FUNCTION FC 38 : VOID
  BEGIN
  NETWORK
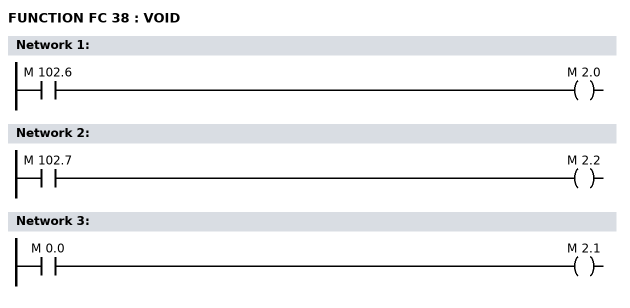
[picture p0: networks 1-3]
       A   M 102.6;
       =   M 2.0;
  NETWORK
       A   M 102.7;
       =   M 2.2;
  NETWORK
       A   M 0.0;
       =   M 2.1;
  NETWORK


END_FUNCTION

FUNCTION FC 39 : VOID
  BEGIN
  NETWORK
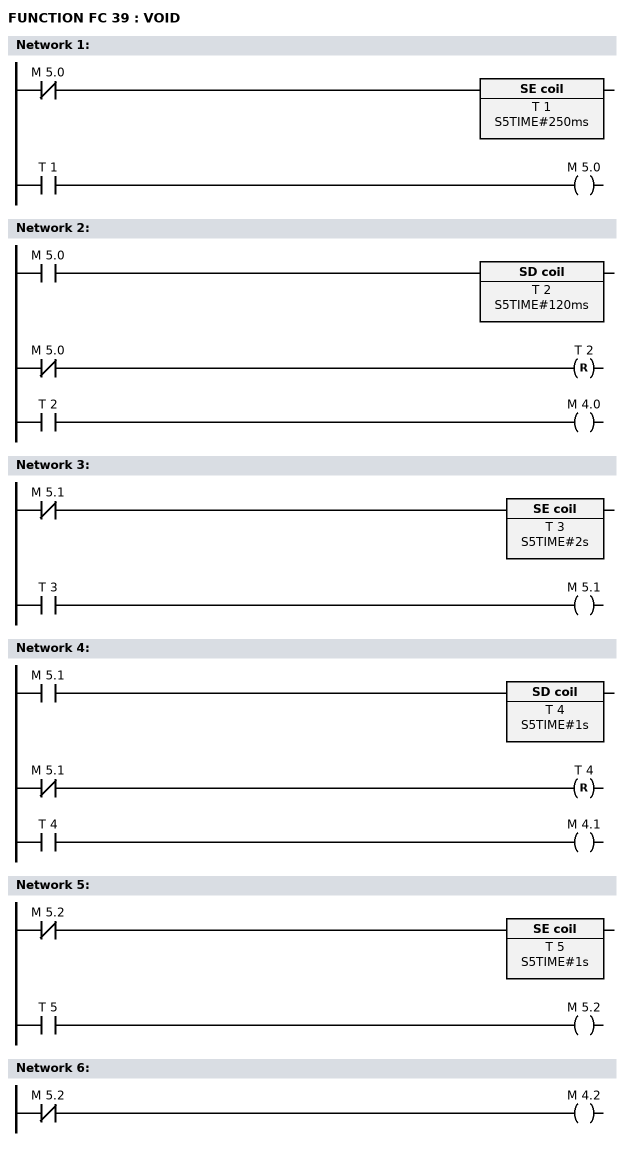
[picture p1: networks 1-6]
       AN  M 5.0;
       L   S5TIME#250ms;
       SE  T 1;
       NOP 0;
       NOP 0;
       NOP 0;
       A   T 1;
       =   M 5.0;
  NETWORK
       A   M 5.0;
       L   S5TIME#120ms;
       SD  T 2;
       AN  M 5.0;
       R   T 2;
       NOP 0;
       NOP 0;
       A   T 2;
       =   M 4.0;
  NETWORK
       AN  M 5.1;
       L   S5TIME#2s;
       SE  T 3;
       NOP 0;
       NOP 0;
       NOP 0;
       A   T 3;
       =   M 5.1;
  NETWORK
       A   M 5.1;
       L   S5TIME#1s;
       SD  T 4;
       AN  M 5.1;
       R   T 4;
       NOP 0;
       NOP 0;
       A   T 4;
       =   M 4.1;
  NETWORK
       AN  M 5.2;
       L   S5TIME#1s;
       SE  T 5;
       NOP 0;
       NOP 0;
       NOP 0;
       A   T 5;
       =   M 5.2;
  NETWORK
       AN  M 5.2;
       =   M 4.2;
  NETWORK


END_FUNCTION

FUNCTION FC 40 : VOID
  BEGIN
  NETWORK
       //;
       AN  M 126.0;
       JCN   X000;
     CALL FC 33;
  X000: NOP 0;
       S   M 126.0;
       //;
       L   W#16#0;
       T   MB 202;
       //;
       //;


END_FUNCTION

FUNCTION FC 41 : VOID
  BEGIN
  NETWORK
       OPN DB 9;
       L   DBW 20;
       T   MW 250;
       L   DBW 22;
       T   MW 252;
       L   DBW 26;
       T   MW 246;
       L   DBW 28;
       T   MW 248;
       //;
       OPN DB 94;
  NETWORK
       A(;
       A   I 14.1;
       =   M 251.0;
       A   M 251.0;
       );
       A   M 250.0;
       S   M 48.1;
  NETWORK
       AN  M 250.0;
       A(;
       AN  M 251.0;
       =   M 250.0;
       A   M 250.0;
       );
       S   M 48.2;
  NETWORK
       A(;
       A   I 14.3;
       =   M 251.2;
       A   M 251.2;
       );
       A   M 250.2;
       S   M 52.1;
  NETWORK
       AN  M 250.2;
       A(;
       AN  M 251.2;
       =   M 250.2;
       A   M 250.2;
       );
       S   M 52.2;
  NETWORK
       AN  M 250.3;
       A(;
       AN  M 181.6;
       =   M 250.3;
       A   M 250.3;
       );
       S   M 66.1;
  NETWORK
       AN  M 251.3;
       A(;
       A   M 181.6;
       =   M 251.3;
       A   M 251.3;
       );
       S   M 66.2;
  NETWORK
       AN  M 250.4;
       A(;
       A   I 29.4;
       A   I 29.5;
       =   M 250.4;
       A   M 250.4;
       );
       S   M 70.1;
  NETWORK
       AN  M 251.4;
       A(;
       AN  I 29.5;
       =   M 251.4;
       A   M 251.4;
       );
       S   M 70.2;
  NETWORK
       AN  M 250.5;
       A(;
       A   I 30.1;
       A   I 36.4;
       =   M 250.5;
       A   M 250.5;
       );
       S   M 71.1;
  NETWORK
       AN  M 251.5;
       A(;
       AN  I 36.4;
       =   M 251.5;
       A   M 251.5;
       );
       S   M 71.2;
  NETWORK
       AN  M 250.5;
       A(;
       A   I 36.6;
       A   I 36.7;
       =   M 250.5;
       A   M 250.5;
       );
       S   M 82.1;
  NETWORK
       AN  M 251.4;
       A(;
       AN  I 36.7;
       =   M 251.4;
       A   M 251.4;
       );
       S   M 82.2;
  NETWORK
       A(;
       O   M 104.0;
       L   DBW 150;
       SF  T 75;
       NOP 0;
       NOP 0;
       NOP 0;
       A   T 75;
       );
       A(;
       O   I 7.1;
       O;
       AN  I 7.0;
       A   M 108.0;
       );
       =   M 253.2;
       A   M 253.2;
       A   M 252.2;
       S   M 114.1;
  NETWORK
       AN  M 252.2;
       A(;
       AN  M 253.2;
       =   M 252.2;
       A   M 252.2;
       );
       S   M 114.2;
  NETWORK
       A(;
       O   M 104.1;
       L   DBW 152;
       SF  T 76;
       NOP 0;
       NOP 0;
       NOP 0;
       A   T 76;
       );
       A(;
       O   I 7.3;
       O;
       AN  I 7.2;
       A   M 108.1;
       );
       =   M 253.3;
       A   M 253.3;
       A   M 252.3;
       S   M 115.1;
  NETWORK
       AN  M 252.3;
       A(;
       AN  M 253.3;
       =   M 252.3;
       A   M 252.3;
       );
       S   M 115.2;
  NETWORK
       A   M 102.1;
       S   M 105.5;
       OPN DB 100;
       A   DBX 24.2;
       R   M 105.5;
  NETWORK
       AN  M 253.4;
       A(;
       A(;
       A   I 25.7;
       L   DBW 218;
       SD  T 109;
       NOP 0;
       NOP 0;
       NOP 0;
       A   T 109;
       );
       AN  M 105.5;
       =   M 253.4;
       A   M 253.4;
       );
       S   M 122.1;
  NETWORK
       AN  M 252.4;
       A(;
       O   M 105.5;
       =   M 252.4;
       A   M 252.4;
       );
       S   M 122.2;
  NETWORK
       AN  M 252.5;
       A(;
       A   M 178.6;
       =   M 252.5;
       A   M 252.5;
       );
       S   M 116.1;
  NETWORK
       AN  M 252.5;
       A(;
       A(;
       AN  M 179.6;
       L   DBW 220;
       SF  T 110;
       NOP 0;
       NOP 0;
       NOP 0;
       A   T 110;
       );
       =   M 252.5;
       A   M 252.5;
       );
       S   M 116.2;
  NETWORK
       OPN DB 110;
       A   DBX 42.0;
       =   M 252.7;
  NETWORK
       OPN DB 94;
       AN  M 252.6;
       A(;
       A(;
       AN  Q 0.2;
       L   DBW 222;
       SD  T 111;
       NOP 0;
       NOP 0;
       NOP 0;
       A   T 111;
       );
       A   M 252.7;
       =   M 252.6;
       A   M 252.6;
       );
       S   M 121.1;
  NETWORK
       AN  M 252.6;
       A(;
       A(;
       A   Q 0.2;
       L   DBW 224;
       SD  T 112;
       NOP 0;
       NOP 0;
       NOP 0;
       A   T 112;
       );
       A   M 252.7;
       =   M 252.6;
       A   M 252.6;
       );
       S   M 121.2;
  NETWORK
       //;
  NETWORK
       AN  M 246.0;
       A(;
       A   I 3.4;
       =   M 246.0;
       A   M 246.0;
       );
       S   M 68.1;
  NETWORK
       //;
       AN  M 247.0;
       A(;
       AN  I 0.6;
       =   M 247.0;
       A   M 247.0;
       );
       S   M 68.2;
  NETWORK
       AN  M 246.1;
       A(;
       A   I 0.2;
       =   M 246.1;
       A   M 246.1;
       );
       S   M 42.1;
  NETWORK
       AN  M 247.1;
       A(;
       AN  I 0.0;
       =   M 247.1;
       A   M 247.1;
       );
       S   M 42.2;
  NETWORK
       AN  M 246.2;
       A(;
       A   I 0.2;
       =   M 246.2;
       A   M 246.2;
       );
       S   M 43.1;
  NETWORK
       //;
       AN  M 247.2;
       A(;
       AN  I 0.0;
       =   M 247.2;
       A   M 247.2;
       );
       S   M 43.2;
  NETWORK
       A(;
       AN  M 0.1;
       =   M 247.3;
       A   M 247.3;
       );
       A   M 246.3;
       S   M 123.1;
  NETWORK
       //;
       AN  M 246.3;
       A(;
       AN  M 247.3;
       =   M 246.3;
       A   M 246.3;
       );
       S   M 123.2;
  NETWORK
       AN  M 247.4;
       A(;
       AN  I 29.0;
       =   M 247.4;
       A   M 247.4;
       );
       A   M 247.4;
       S   M 118.2;
  NETWORK
       //;
       AN  M 246.4;
       A(;
       A   I 29.1;
       =   M 246.4;
       A   M 246.4;
       );
       S   M 118.1;
  NETWORK
       AN  M 247.5;
       A(;
       AN  I 29.0;
       =   M 247.5;
       A   M 247.5;
       );
       A   M 247.5;
       S   M 119.2;
  NETWORK
       //;
       AN  M 246.5;
       A(;
       A   I 29.1;
       =   M 246.5;
       A   M 246.5;
       );
       S   M 119.1;
       //;
  NETWORK
       OPN DB 9;
       L   MW 250;
       T   DBW 20;
       L   MW 252;
       T   DBW 22;
       L   MW 246;
       T   DBW 26;
       L   MW 248;
       T   DBW 28;
       //;
       OPN DB 94;
  NETWORK
       //;
       //;
       //;
       //;
       //;
       //;
       //;
       //;
  NETWORK


END_FUNCTION

FUNCTION FC 42 : VOID
  BEGIN
  NETWORK
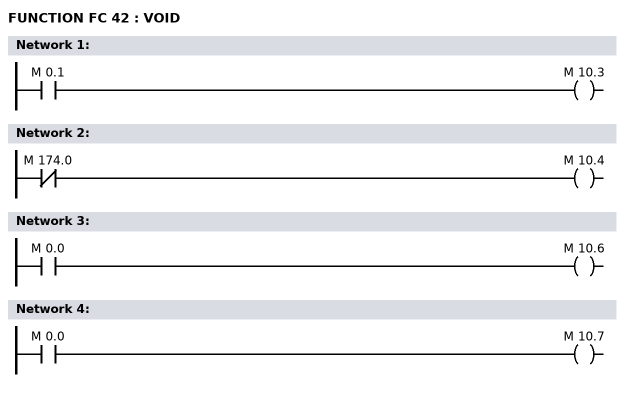
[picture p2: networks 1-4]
       O   M 0.1;
       =   M 10.3;
  NETWORK
       AN  M 174.0;
       =   M 10.4;
  NETWORK
       A   M 0.0;
       =   M 10.6;
  NETWORK
       A   M 0.0;
       =   M 10.7;
  NETWORK
       OPN DB 100;
       L   DBW 20;
       T   MW 206;
       L   DBW 220;
       T   MW 204;
       L   MB 10;
       T   MB 200;
       A   Q 5.6;
       =   M 201.0;
       A   M 2.1;
       =   M 201.1;
       A   I 26.7;
       =   M 201.2;
       A   M 0.0;
       =   M 201.3;
  NETWORK
       CALL FC 15;
  NETWORK
       A   M 201.0;
       =   Q 5.6;
       L   MB 200;
       T   MB 10;
       L   MW 204;
       T   DBW 220;
       L   MW 206;
       T   DBW 20;
  NETWORK
       OPN DB 108;
       L   MB 202;
       T   DBB 21;


END_FUNCTION

FUNCTION FC 43 : VOID
  BEGIN
  NETWORK
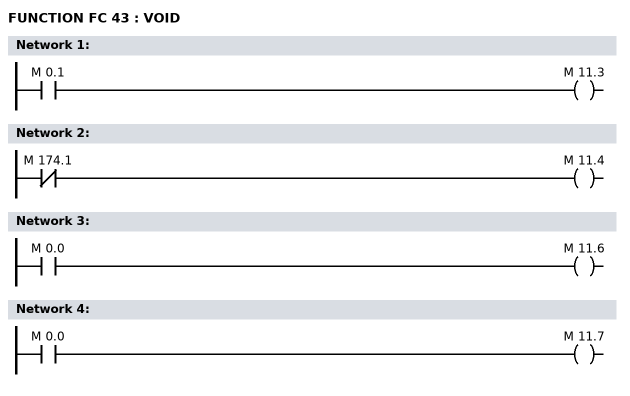
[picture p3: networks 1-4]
       A   M 0.1;
       =   M 11.3;
  NETWORK
       AN  M 174.1;
       =   M 11.4;
  NETWORK
       A   M 0.0;
       =   M 11.6;
  NETWORK
       A   M 0.0;
       =   M 11.7;
  NETWORK
       OPN DB 100;
       L   DBW 22;
       T   MW 206;
       L   DBW 222;
       T   MW 204;
       L   MB 11;
       T   MB 200;
       A   Q 10.4;
       =   M 201.0;
       A   M 2.1;
       =   M 201.1;
       A   I 27.7;
       =   M 201.2;
       A   M 0.0;
       =   M 201.3;
  NETWORK
       CALL FC 15;
  NETWORK
       A   M 201.0;
       =   Q 10.4;
       L   MB 200;
       T   MB 11;
       L   MW 204;
       T   DBW 222;
       L   MW 206;
       T   DBW 22;
  NETWORK
       OPN DB 108;
       L   MB 202;
       T   DBB 20;
END_FUNCTION


FUNCTION FC 44 : VOID
  BEGIN
  NETWORK
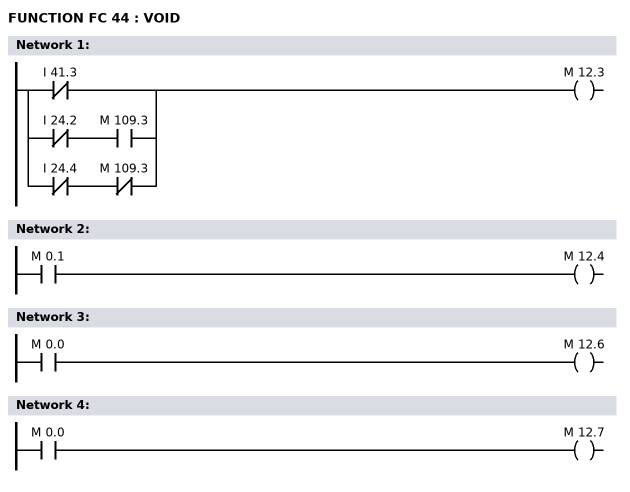
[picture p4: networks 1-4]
       ON  I 41.3;
       O(;
       AN  I 24.2;
       A   M 109.3;
       );
       O(;
       ON  I 24.4;
       AN  M 109.3;
       );
       =   M 12.3;
  NETWORK
       A   M 0.1;
       =   M 12.4;
  NETWORK
       A   M 0.0;
       =   M 12.6;
  NETWORK
       A   M 0.0;
       =   M 12.7;
  NETWORK
       OPN DB 100;
       L   DBW 24;
       T   MW 206;
       L   DBW 224;
       T   MW 204;
       L   MB 12;
       T   MB 200;
       A   Q 4.0;
       =   M 201.0;
       A   M 2.1;
       =   M 201.1;
       A   I 25.7;
       =   M 201.2;
       A   M 0.0;
       =   M 201.3;
  NETWORK
       CALL FC 15;
  NETWORK
       A   M 201.0;
       =   Q 4.0;
       L   MB 200;
       T   MB 12;
       L   MW 204;
       T   DBW 224;
       L   MW 206;
       T   DBW 24;
  NETWORK
       OPN DB 108;
       L   MB 202;
       T   DBB 23;


END_FUNCTION

FUNCTION FC 45 : VOID
  BEGIN
  NETWORK
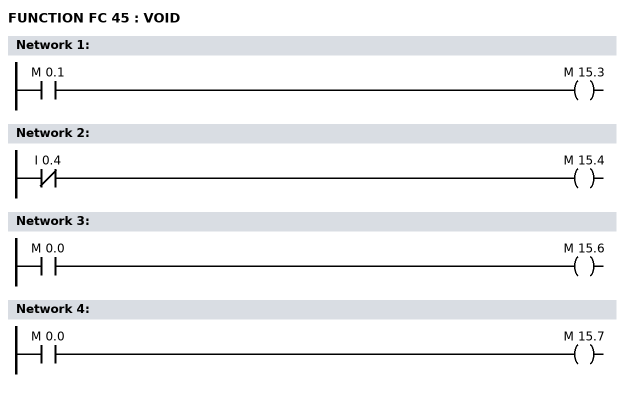
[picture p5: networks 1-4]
       A   M 0.1;
       =   M 15.3;
  NETWORK
       AN  I 0.4;
       =   M 15.4;
  NETWORK
       A   M 0.0;
       =   M 15.6;
  NETWORK
       A   M 0.0;
       =   M 15.7;
  NETWORK
       OPN DB 100;
       L   DBW 30;
       T   MW 206;
       L   DBW 230;
       T   MW 204;
       L   MB 15;
       T   MB 200;
       A   Q 0.5;
       =   M 201.0;
       A   M 2.1;
       =   M 201.1;
       A   I 0.5;
       =   M 201.2;
       A   M 0.0;
       =   M 201.3;
  NETWORK
       CALL FC 15;
  NETWORK
       A   M 201.0;
       =   Q 0.5;
       L   MB 200;
       T   MB 15;
       L   MW 204;
       T   DBW 230;
       L   MW 206;
       T   DBW 30;
  NETWORK
       OPN DB 108;
       L   MB 202;
       T   DBB 24;


END_FUNCTION

FUNCTION FC 46 : VOID
  BEGIN
  NETWORK
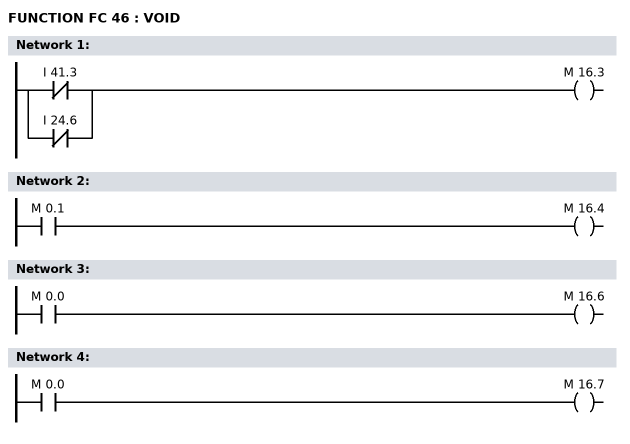
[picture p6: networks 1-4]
       ON  I 41.3;
       ON  I 24.6;
       =   M 16.3;
  NETWORK
       A   M 0.1;
       =   M 16.4;
  NETWORK
       A   M 0.0;
       =   M 16.6;
  NETWORK
       A   M 0.0;
       =   M 16.7;
  NETWORK
       OPN DB 100;
       L   DBW 32;
       T   MW 206;
       L   DBW 232;
       T   MW 204;
       L   MB 16;
       T   MB 200;
       A   Q 4.2;
       =   M 201.0;
       A   M 2.1;
       =   M 201.1;
       A   I 26.3;
       =   M 201.2;
       A   M 0.0;
       =   M 201.3;
  NETWORK
       CALL FC 15;
  NETWORK
       A   M 201.0;
       =   Q 4.2;
       L   MB 200;
       T   MB 16;
       L   MW 204;
       T   DBW 232;
       L   MW 206;
       T   DBW 32;
  NETWORK
       OPN DB 108;
       L   MB 202;
       T   DBB 27;


END_FUNCTION

FUNCTION FC 47 : VOID
  BEGIN
  NETWORK
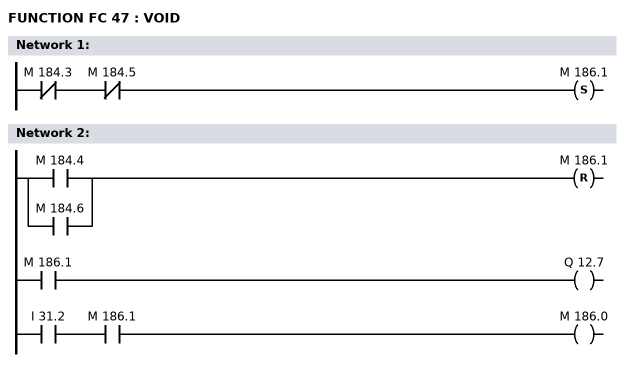
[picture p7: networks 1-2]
       AN  M 184.3;
       AN  M 184.5;
       S   M 186.1;
  NETWORK
       O   M 184.4;
       O   M 184.6;
       R   M 186.1;
       A   M 186.1;
       =   Q 12.7;
       A   I 31.2;
       A   M 186.1;
       =   M 186.0;


END_FUNCTION

FUNCTION FC 48 : VOID
  BEGIN
  NETWORK
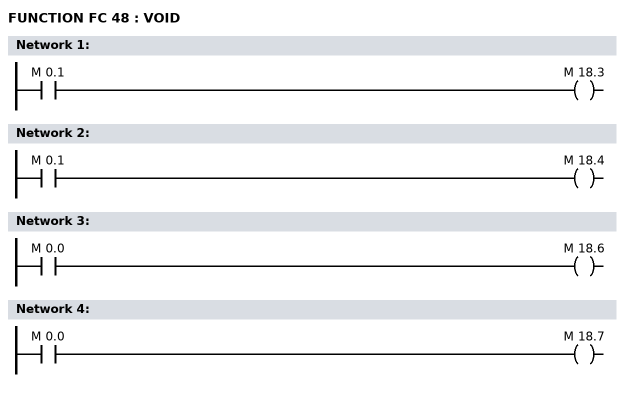
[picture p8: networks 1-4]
       A   M 0.1;
       =   M 18.3;
  NETWORK
       A   M 0.1;
       =   M 18.4;
  NETWORK
       A   M 0.0;
       =   M 18.6;
  NETWORK
       A   M 0.0;
       =   M 18.7;
  NETWORK
       OPN DB 100;
       L   DBW 36;
       T   MW 206;
       L   DBW 236;
       T   MW 204;
       L   MB 18;
       T   MB 200;
       A   Q 1.0;
       =   M 201.0;
       A   M 2.1;
       =   M 201.1;
       A   I 1.0;
       =   M 201.2;
       A   M 0.0;
       =   M 201.3;
  NETWORK
       CALL FC 15;
  NETWORK
       A   M 201.0;
       =   Q 1.0;
       L   MB 200;
       T   MB 18;
       L   MW 204;
       T   DBW 236;
       L   MW 206;
       T   DBW 36;
  NETWORK
       OPN DB 108;
       L   MB 202;
       T   DBB 29;


END_FUNCTION

FUNCTION FC 49 : VOID
  BEGIN
  NETWORK
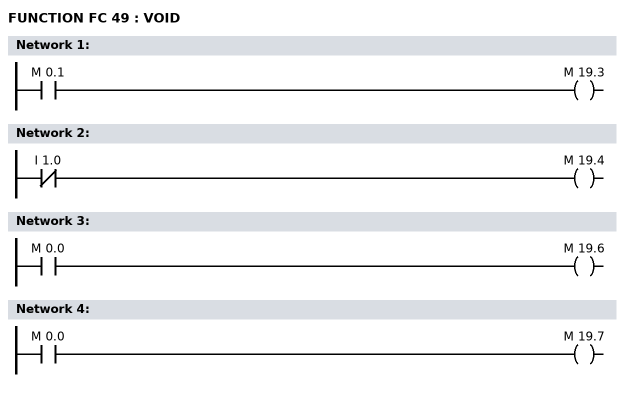
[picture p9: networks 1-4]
       A   M 0.1;
       =   M 19.3;
  NETWORK
       AN  I 1.0;
       =   M 19.4;
  NETWORK
       A   M 0.0;
       =   M 19.6;
  NETWORK
       A   M 0.0;
       =   M 19.7;
  NETWORK
       OPN DB 100;
       L   DBW 38;
       T   MW 206;
       L   DBW 238;
       T   MW 204;
       L   MB 19;
       T   MB 200;
       A   Q 1.1;
       =   M 201.0;
       A   M 2.1;
       =   M 201.1;
       A   I 1.1;
       =   M 201.2;
       A   M 0.0;
       =   M 201.3;
  NETWORK
       CALL FC 15;
  NETWORK
       A   M 201.0;
       =   Q 1.1;
       L   MB 200;
       T   MB 19;
       L   MW 204;
       T   DBW 238;
       L   MW 206;
       T   DBW 38;
  NETWORK
       OPN DB 108;
       L   MB 202;
       T   DBB 28;


END_FUNCTION

FUNCTION FC 50 : VOID
  BEGIN
  NETWORK
       OPN DB 94;
  NETWORK
       AN  I 7.0;
       AN  I 7.1;
       =   M 24.3;
  NETWORK
       O(;
       AN  M 114.4;
       AN  M 114.5;
       L   DBW 40;
       SD  T 20;
       NOP 0;
       NOP 0;
       NOP 0;
       A   T 20;
       );
       ON  I 3.2;
       L   DBW 60;
       SF  T 30;
       NOP 0;
       NOP 0;
       NOP 0;
       A   T 30;
       =   M 24.4;
  NETWORK
       A   M 0.0;
       =   M 24.6;
  NETWORK
       A   M 0.0;
       =   M 24.7;
  NETWORK
       OPN DB 100;
       L   DBW 48;
       T   MW 206;
       L   DBW 248;
       T   MW 204;
       L   MB 24;
       T   MB 200;
       A   Q 1.6;
       =   M 201.0;
       A   M 2.1;
       =   M 201.1;
       A   I 1.6;
       =   M 201.2;
       A   M 0.0;
       =   M 201.3;
  NETWORK
       CALL FC 15;
  NETWORK
       A   M 201.0;
       =   Q 1.6;
       L   MB 200;
       T   MB 24;
       L   MW 204;
       T   DBW 248;
       L   MW 206;
       T   DBW 48;
  NETWORK
       OPN DB 108;
       L   MB 202;
       T   DBB 35;


END_FUNCTION

FUNCTION FC 51 : VOID
  BEGIN
  NETWORK
       OPN DB 94;
  NETWORK
       A   M 0.1;
       =   M 25.3;
  NETWORK
       O(;
       A   I 8.6;
       L   DBW 62;
       SF  T 31;
       NOP 0;
       NOP 0;
       NOP 0;
       A   T 31;
       );
       O;
       AN  M 112.4;
       AN  M 113.5;
       ON  I 3.3;
       L   DBW 90;
       SF  T 45;
       NOP 0;
       NOP 0;
       NOP 0;
       A   T 45;
       =   M 25.4;
  NETWORK
       A   M 0.0;
       =   M 25.6;
  NETWORK
       A   M 0.0;
       =   M 25.7;
  NETWORK
       OPN DB 100;
       L   DBW 50;
       T   MW 206;
       L   DBW 250;
       T   MW 204;
       L   MB 25;
       T   MB 200;
       A   Q 1.7;
       =   M 201.0;
       A   M 2.1;
       =   M 201.1;
       A   I 1.7;
       =   M 201.2;
       A   M 0.0;
       =   M 201.3;
  NETWORK
       CALL FC 15;
  NETWORK
       A   M 201.0;
       =   Q 1.7;
       L   MB 200;
       T   MB 25;
       L   MW 204;
       T   DBW 250;
       L   MW 206;
       T   DBW 50;
  NETWORK
       OPN DB 108;
       L   MB 202;
       T   DBB 34;


END_FUNCTION

FUNCTION FC 52 : VOID
  BEGIN
  NETWORK
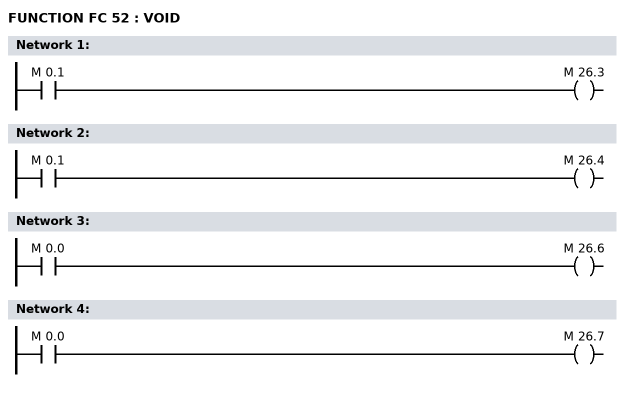
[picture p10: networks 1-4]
       A   M 0.1;
       =   M 26.3;
  NETWORK
       A   M 0.1;
       =   M 26.4;
  NETWORK
       A   M 0.0;
       =   M 26.6;
  NETWORK
       A   M 0.0;
       =   M 26.7;
  NETWORK
       OPN DB 100;
       L   DBW 52;
       T   MW 206;
       L   DBW 252;
       T   MW 204;
       L   MB 26;
       T   MB 200;
       A   Q 2.0;
       =   M 201.0;
       A   M 2.1;
       =   M 201.1;
       A   I 2.0;
       =   M 201.2;
       A   M 0.0;
       =   M 201.3;
  NETWORK
       CALL FC 15;
  NETWORK
       A   M 201.0;
       =   Q 2.0;
       L   MB 200;
       T   MB 26;
       L   MW 204;
       T   DBW 252;
       L   MW 206;
       T   DBW 52;
  NETWORK
       OPN DB 108;
       L   MB 202;
       T   DBB 37;


END_FUNCTION

FUNCTION FC 53 : VOID
  BEGIN
  NETWORK
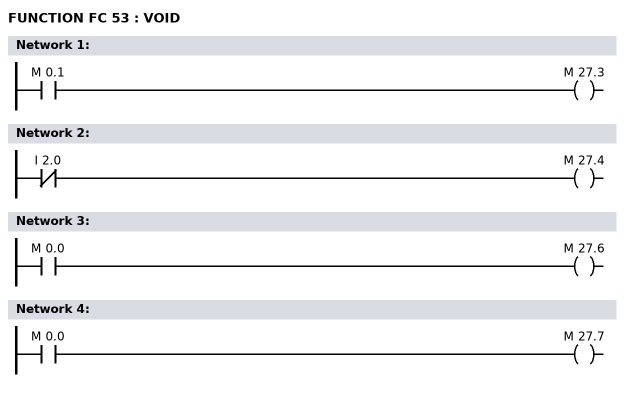
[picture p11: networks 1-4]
       A   M 0.1;
       =   M 27.3;
  NETWORK
       AN  I 2.0;
       =   M 27.4;
  NETWORK
       A   M 0.0;
       =   M 27.6;
  NETWORK
       A   M 0.0;
       =   M 27.7;
  NETWORK
       OPN DB 100;
       L   DBW 54;
       T   MW 206;
       L   DBW 254;
       T   MW 204;
       L   MB 27;
       T   MB 200;
       O   Q 2.1;
       =   M 201.0;
       A   M 2.1;
       =   M 201.1;
       A   I 2.1;
       =   M 201.2;
       A   M 0.0;
       =   M 201.3;
  NETWORK
       CALL FC 15;
  NETWORK
       A   M 201.0;
       =   Q 2.1;
       L   MB 200;
       T   MB 27;
       L   MW 204;
       T   DBW 254;
       L   MW 206;
       T   DBW 54;
  NETWORK
       OPN DB 108;
       L   MB 202;
       T   DBB 36;


END_FUNCTION

FUNCTION FC 54 : VOID
  BEGIN
  NETWORK
       OPN DB 94;
  NETWORK
       AN  I 7.2;
       AN  I 7.3;
       =   M 35.3;
  NETWORK
       O(;
       AN  M 115.4;
       AN  M 115.5;
       L   DBW 70;
       SD  T 35;
       NOP 0;
       NOP 0;
       NOP 0;
       A   T 35;
       );
       O;
       ON  I 3.3;
       L   DBW 72;
       SF  T 36;
       NOP 0;
       NOP 0;
       NOP 0;
       A   T 36;
       =   M 35.4;
  NETWORK
       A   M 0.0;
       =   M 35.6;
  NETWORK
       A   M 0.0;
       =   M 35.7;
  NETWORK
       OPN DB 100;
       L   DBW 70;
       T   MW 206;
       L   DBW 270;
       T   MW 204;
       L   MB 35;
       T   MB 200;
       A   Q 3.1;
       =   M 201.0;
       A   M 2.1;
       =   M 201.1;
       A   I 3.1;
       =   M 201.2;
       A   M 0.0;
       =   M 201.3;
  NETWORK
       CALL FC 15;
  NETWORK
       A   M 201.0;
       =   Q 3.1;
       L   MB 200;
       T   MB 35;
       L   MW 204;
       T   DBW 270;
       L   MW 206;
       T   DBW 70;
  NETWORK
       OPN DB 108;
       L   MB 202;
       T   DBB 44;


END_FUNCTION

FUNCTION FC 55 : VOID
  BEGIN
  NETWORK
       OPN DB 94;
  NETWORK
       A   M 0.1;
       =   M 36.3;
  NETWORK
       A(;
       AN  I 7.0;
       AN  I 7.1;
       L   DBW 74;
       SD  T 37;
       NOP 0;
       NOP 0;
       NOP 0;
       A   T 37;
       );
       ON  I 1.1;
       =   M 36.4;
  NETWORK
       A   M 0.0;
       =   M 36.6;
  NETWORK
       AN  I 1.6;
       =   M 36.7;
  NETWORK
       OPN DB 100;
       L   DBW 72;
       T   MW 206;
       L   DBW 272;
       T   MW 204;
       L   MB 36;
       T   MB 200;
       A   Q 3.2;
       =   M 201.0;
       A   M 2.1;
       =   M 201.1;
       A   I 3.2;
       =   M 201.2;
       A   M 0.0;
       =   M 201.3;
  NETWORK
       CALL FC 15;
  NETWORK
       A   M 201.0;
       =   Q 3.2;
       L   MB 200;
       T   MB 36;
       L   MW 204;
       T   DBW 272;
       L   MW 206;
       T   DBW 72;
  NETWORK
       OPN DB 108;
       L   MB 202;
       T   DBB 47;


END_FUNCTION

FUNCTION FC 56 : VOID
  BEGIN
  NETWORK
       OPN DB 94;
  NETWORK
       A   M 0.1;
       =   M 37.3;
  NETWORK
       O(;
       AN  I 7.6;
       AN  I 7.7;
       L   DBW 80;
       SF  T 40;
       NOP 0;
       NOP 0;
       NOP 0;
       A   T 40;
       );
       ON  I 2.1;
       =   M 37.4;
  NETWORK
       A   M 0.0;
       =   M 37.6;
  NETWORK
       AN  I 3.1;
       =   M 37.7;
  NETWORK
       OPN DB 100;
       L   DBW 74;
       T   MW 206;
       L   DBW 274;
       T   MW 204;
       L   MB 37;
       T   MB 200;
       A   Q 3.3;
       =   M 201.0;
       A   M 2.1;
       =   M 201.1;
       A   I 3.3;
       =   M 201.2;
       A   M 0.0;
       =   M 201.3;
  NETWORK
       CALL FC 15;
  NETWORK
       A   M 201.0;
       =   Q 3.3;
       L   MB 200;
       T   MB 37;
       L   MW 204;
       T   DBW 274;
       L   MW 206;
       T   DBW 74;
  NETWORK
       OPN DB 108;
       L   MB 202;
       T   DBB 46;


END_FUNCTION

FUNCTION FC 57 : VOID
  BEGIN
  NETWORK
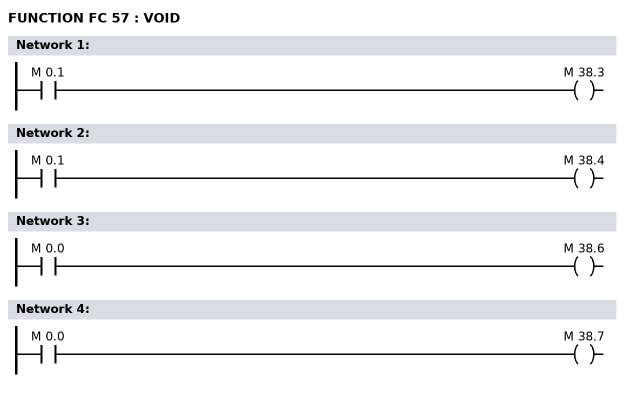
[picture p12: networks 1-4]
       A   M 0.1;
       =   M 38.3;
  NETWORK
       A   M 0.1;
       =   M 38.4;
  NETWORK
       A   M 0.0;
       =   M 38.6;
  NETWORK
       A   M 0.0;
       =   M 38.7;
  NETWORK
       OPN DB 100;
       L   DBW 76;
       T   MW 206;
       L   DBW 276;
       T   MW 204;
       L   MB 38;
       T   MB 200;
       A   Q 3.4;
       =   M 201.0;
       A   M 2.1;
       =   M 201.1;
       A   I 3.4;
       =   M 201.2;
       A   M 0.0;
       =   M 201.3;
  NETWORK
       CALL FC 15;
  NETWORK
       A   M 201.0;
       =   Q 3.4;
       L   MB 200;
       T   MB 38;
       L   MW 204;
       T   DBW 276;
       L   MW 206;
       T   DBW 76;
  NETWORK
       OPN DB 108;
       L   MW 202;
       T   DBB 49;


END_FUNCTION

FUNCTION FC 58 : VOID
  BEGIN
  NETWORK
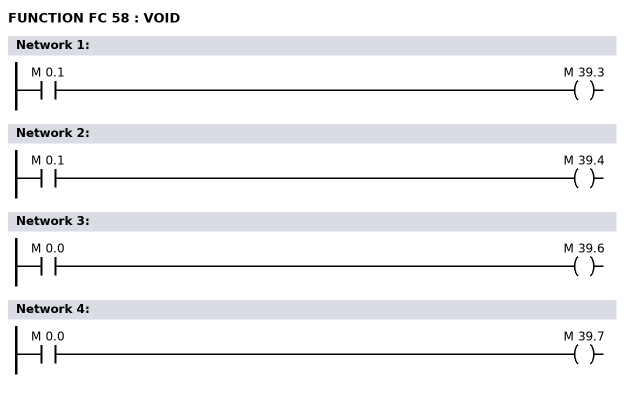
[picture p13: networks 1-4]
       A   M 0.1;
       =   M 39.3;
  NETWORK
       A   M 0.1;
       =   M 39.4;
  NETWORK
       A   M 0.0;
       =   M 39.6;
  NETWORK
       A   M 0.0;
       =   M 39.7;
  NETWORK
       OPN DB 100;
       L   DBW 78;
       T   MW 206;
       L   DBW 278;
       T   MW 204;
       L   MB 39;
       T   MB 200;
       A   Q 3.5;
       =   M 201.0;
       A   M 2.1;
       =   M 201.1;
       A   I 3.5;
       =   M 201.2;
       A   M 0.0;
       =   M 201.3;
  NETWORK
       CALL FC 15;
  NETWORK
       A   M 201.0;
       =   Q 3.5;
       L   MB 200;
       T   MB 39;
       L   MW 204;
       T   DBW 278;
       L   MW 206;
       T   DBW 78;
  NETWORK
       OPN DB 108;
       L   MW 202;
       T   DBB 48;


END_FUNCTION

FUNCTION FC 59 : VOID
  BEGIN
  NETWORK
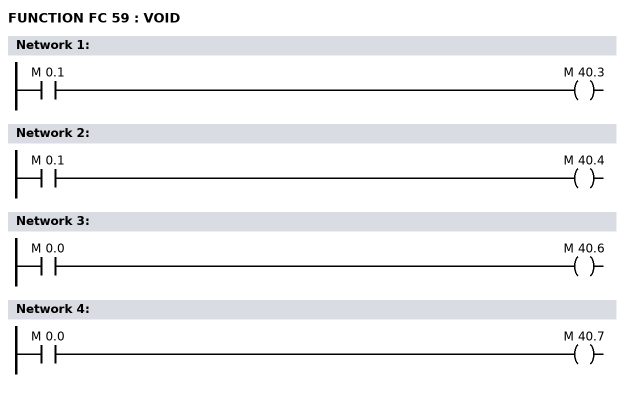
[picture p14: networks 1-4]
       A   M 0.1;
       =   M 40.3;
  NETWORK
       A   M 0.1;
       =   M 40.4;
  NETWORK
       A   M 0.0;
       =   M 40.6;
  NETWORK
       A   M 0.0;
       =   M 40.7;
  NETWORK
       OPN DB 100;
       L   DBW 80;
       T   MW 206;
       L   DBW 280;
       T   MW 204;
       L   MB 40;
       T   MB 200;
       A   Q 3.6;
       =   M 201.0;
       A   M 2.1;
       =   M 201.1;
       A   I 3.6;
       =   M 201.2;
       A   M 0.0;
       =   M 201.3;
  NETWORK
       CALL FC 15;
  NETWORK
       A   M 201.0;
       =   Q 3.6;
       L   MB 200;
       T   MB 40;
       L   MW 204;
       T   DBW 280;
       L   MW 206;
       T   DBW 80;
  NETWORK
       OPN DB 108;
       L   MW 202;
       T   DBB 51;


END_FUNCTION

FUNCTION FC 60 : VOID
  BEGIN
  NETWORK
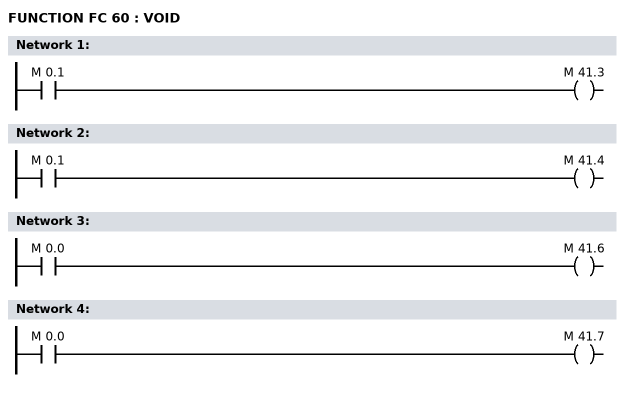
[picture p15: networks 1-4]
       A   M 0.1;
       =   M 41.3;
  NETWORK
       A   M 0.1;
       =   M 41.4;
  NETWORK
       A   M 0.0;
       =   M 41.6;
  NETWORK
       A   M 0.0;
       =   M 41.7;
  NETWORK
       OPN DB 100;
       L   DBW 82;
       T   MW 206;
       L   DBW 282;
       T   MW 204;
       L   MB 41;
       T   MB 200;
       A   Q 3.7;
       =   M 201.0;
       A   M 2.1;
       =   M 201.1;
       A   I 3.7;
       =   M 201.2;
       A   M 0.0;
       =   M 201.3;
  NETWORK
       CALL FC 15;
  NETWORK
       A   M 201.0;
       =   Q 3.7;
       L   MB 200;
       T   MB 41;
       L   MW 204;
       T   DBW 282;
       L   MW 206;
       T   DBW 82;
  NETWORK
       OPN DB 108;
       L   MW 202;
       T   DBB 50;


END_FUNCTION

FUNCTION FC 61 : VOID
  BEGIN
  NETWORK
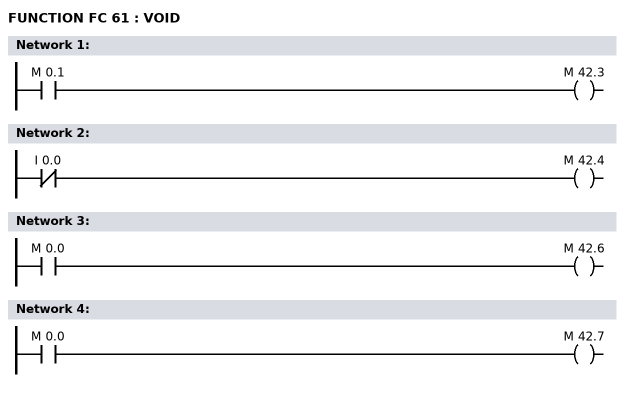
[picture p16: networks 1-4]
       A   M 0.1;
       =   M 42.3;
  NETWORK
       AN  I 0.0;
       =   M 42.4;
  NETWORK
       A   M 0.0;
       =   M 42.6;
  NETWORK
       A   M 0.0;
       =   M 42.7;
  NETWORK
       OPN DB 100;
       L   DBW 84;
       T   MW 206;
       L   DBW 284;
       T   MW 204;
       L   MB 42;
       T   MB 200;
       A   Q 6.0;
       =   M 201.0;
       A   M 2.1;
       =   M 201.1;
       A   I 12.0;
       =   M 201.2;
       A   M 0.0;
       =   M 201.3;
  NETWORK
       CALL FC 15;
  NETWORK
       A   M 201.0;
       =   Q 6.0;
       L   MB 200;
       T   MB 42;
       L   MW 204;
       T   DBW 284;
       L   MW 206;
       T   DBW 84;
  NETWORK
       OPN DB 108;
       L   MB 202;
       T   DBB 53;


END_FUNCTION

FUNCTION FC 62 : VOID
  BEGIN
  NETWORK
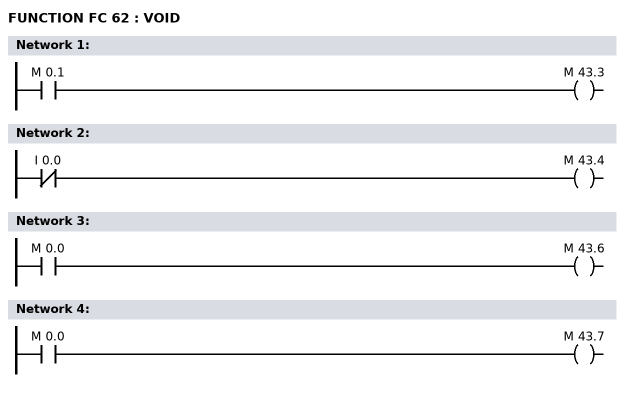
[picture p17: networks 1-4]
       A   M 0.1;
       =   M 43.3;
  NETWORK
       AN  I 0.0;
       =   M 43.4;
  NETWORK
       A   M 0.0;
       =   M 43.6;
  NETWORK
       A   M 0.0;
       =   M 43.7;
  NETWORK
       OPN DB 100;
       L   DBW 86;
       T   MW 206;
       L   DBW 286;
       T   MW 204;
       L   MB 43;
       T   MB 200;
       A   Q 6.1;
       =   M 201.0;
       A   M 2.1;
       =   M 201.1;
       A   I 12.1;
       =   M 201.2;
       A   M 0.0;
       =   M 201.3;
  NETWORK
       CALL FC 15;
  NETWORK
       A   M 201.0;
       =   Q 6.1;
       L   MB 200;
       T   MB 43;
       L   MW 204;
       T   DBW 286;
       L   MW 206;
       T   DBW 86;
  NETWORK
       OPN DB 108;
       L   MB 202;
       T   DBB 52;


END_FUNCTION

FUNCTION FC 63 : VOID
  BEGIN
  NETWORK
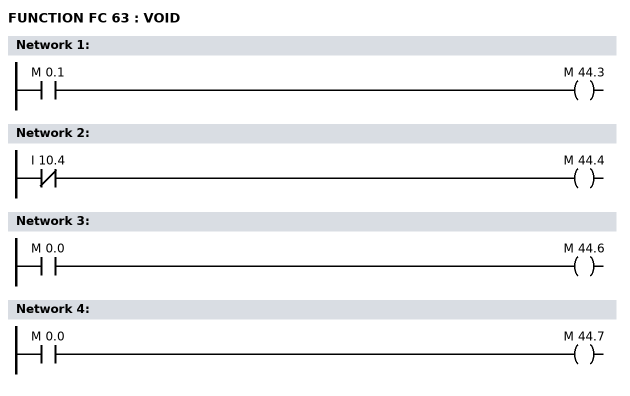
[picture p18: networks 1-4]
       A   M 0.1;
       =   M 44.3;
  NETWORK
       AN  I 10.4;
       =   M 44.4;
  NETWORK
       A   M 0.0;
       =   M 44.6;
  NETWORK
       A   M 0.0;
       =   M 44.7;
  NETWORK
       OPN DB 100;
       L   DBW 88;
       T   MW 206;
       L   DBW 288;
       T   MW 204;
       L   MB 44;
       T   MB 200;
       A   Q 4.3;
       =   M 201.0;
       A   M 2.1;
       =   M 201.1;
       A   I 26.6;
       =   M 201.2;
       A   M 0.0;
       =   M 201.3;
  NETWORK
       CALL FC 15;
  NETWORK
       A   M 201.0;
       =   Q 4.3;
       L   MB 200;
       T   MB 44;
       L   MW 204;
       T   DBW 288;
       L   MW 206;
       T   DBW 88;
  NETWORK
       OPN DB 108;
       L   MB 202;
       T   DBB 55;


END_FUNCTION

FUNCTION FC 64 : VOID
  BEGIN
  NETWORK
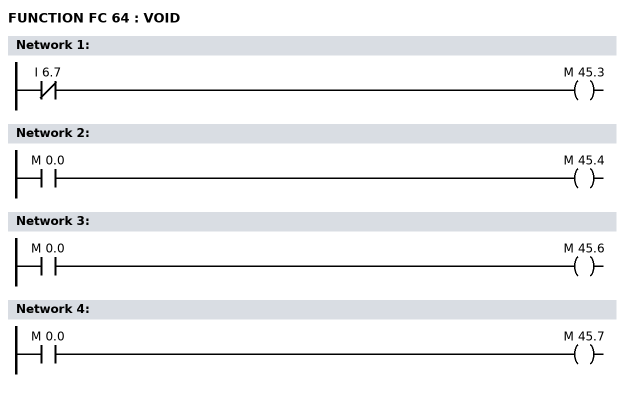
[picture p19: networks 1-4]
       AN  I 6.7;
       =   M 45.3;
  NETWORK
       A   M 0.0;
       =   M 45.4;
  NETWORK
       A   M 0.0;
       =   M 45.6;
  NETWORK
       A   M 0.0;
       =   M 45.7;
  NETWORK
       OPN DB 100;
       L   DBW 90;
       T   MW 206;
       L   DBW 290;
       T   MW 204;
       L   MB 45;
       T   MB 200;
       A   Q 17.0;
       =   M 201.0;
       A   M 2.1;
       =   M 201.1;
       A   I 10.4;
       =   M 201.2;
       A   M 0.0;
       =   M 201.3;
  NETWORK
       CALL FC 15;
  NETWORK
       A   M 201.0;
       =   Q 17.0;
       L   MB 200;
       T   MB 45;
       L   MW 204;
       T   DBW 290;
       L   MW 206;
       T   DBW 90;
  NETWORK
       OPN DB 108;
       L   MB 202;
       T   DBB 54;


END_FUNCTION

FUNCTION FC 65 : VOID
  BEGIN
  NETWORK
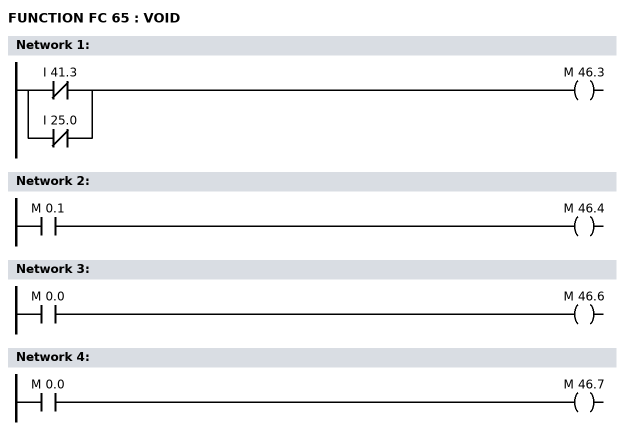
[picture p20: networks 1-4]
       ON  I 41.3;
       ON  I 25.0;
       =   M 46.3;
  NETWORK
       A   M 0.1;
       =   M 46.4;
  NETWORK
       A   M 0.0;
       =   M 46.6;
  NETWORK
       A   M 0.0;
       =   M 46.7;
  NETWORK
       OPN DB 100;
       L   DBW 92;
       T   MW 206;
       L   DBW 292;
       T   MW 204;
       L   MB 46;
       T   MB 200;
       A   Q 10.3;
       =   M 201.0;
       A   M 2.1;
       =   M 201.1;
       A   I 27.6;
       =   M 201.2;
       A   M 0.0;
       =   M 201.3;
  NETWORK
       CALL FC 15;
  NETWORK
       A   M 201.0;
       =   Q 10.3;
       L   MB 200;
       T   MB 46;
       L   MW 204;
       T   DBW 292;
       L   MW 206;
       T   DBW 92;
  NETWORK
       OPN DB 108;
       L   MB 202;
       T   DBB 57;


END_FUNCTION

FUNCTION FC 66 : VOID
  BEGIN
  NETWORK
       AN  I 12.5;
       =   M 47.3;
  NETWORK
       A   M 0.1;
       =   M 47.4;
  NETWORK
       OPN DB 100;
  NETWORK
       A   M 0.0;
       =   M 47.6;
  NETWORK
       A   M 0.0;
       =   M 47.7;
  NETWORK
       OPN DB 100;
       L   DBW 94;
       T   MW 206;
       L   DBW 294;
       T   MW 204;
       L   MB 47;
       T   MB 200;
       A   Q 6.5;
       =   M 201.0;
       A   M 2.1;
       =   M 201.1;
       A   I 12.5;
       =   M 201.2;
       A   M 0.0;
       =   M 201.3;
  NETWORK
       CALL FC 15;
  NETWORK
       A   M 201.0;
       =   Q 6.5;
       L   MB 200;
       T   MB 47;
       L   MW 204;
       T   DBW 294;
       L   MW 206;
       T   DBW 94;
  NETWORK
       OPN DB 108;
       L   MB 202;
       T   DBB 56;


END_FUNCTION


FUNCTION FC 67 : VOID
  BEGIN
  NETWORK
  TITLE = ;MA-158
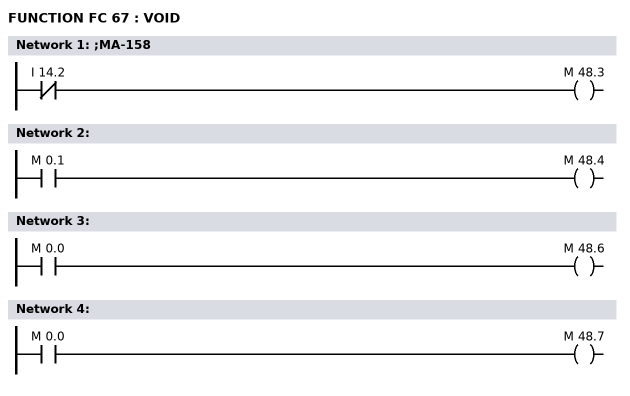
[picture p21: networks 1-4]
       AN  I 14.2;
       =   M 48.3;
  NETWORK
       A   M 0.1;
       =   M 48.4;
  NETWORK
       A   M 0.0;
       =   M 48.6;
  NETWORK
       A   M 0.0;
       =   M 48.7;
  NETWORK
       OPN DB 100;
       L   DBW 96;
       T   MW 206;
       L   DBW 296;
       T   MW 204;
       L   MB 48;
       T   MB 200;
       A   Q 6.6;
       =   M 201.0;
       A   M 2.1;
       =   M 201.1;
       A   I 12.6;
       =   M 201.2;
       A   M 0.0;
       =   M 201.3;
  NETWORK
       CALL FC 15;
  NETWORK
       A   M 201.0;
       =   Q 6.6;
       L   MB 200;
       T   MB 48;
       L   MW 204;
       T   DBW 296;
       L   MW 206;
       T   DBW 96;
  NETWORK
       OPN DB 108;
       L   MB 202;
       T   DBB 59;


END_FUNCTION

FUNCTION FC 68 : VOID
  BEGIN
  NETWORK
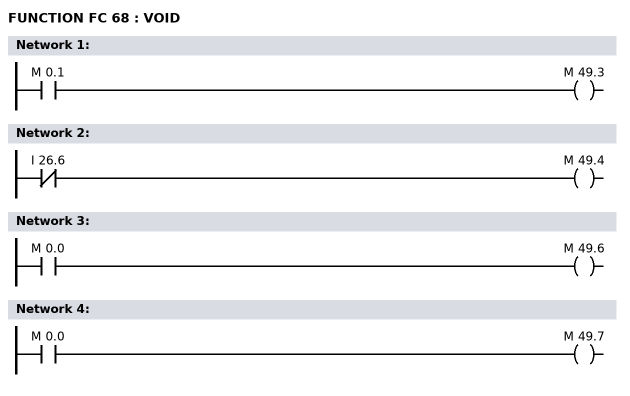
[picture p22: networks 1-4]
       A   M 0.1;
       =   M 49.3;
  NETWORK
       AN  I 26.6;
       =   M 49.4;
  NETWORK
       A   M 0.0;
       =   M 49.6;
  NETWORK
       A   M 0.0;
       =   M 49.7;
  NETWORK
       OPN DB 100;
       L   DBW 98;
       T   MW 206;
       L   DBW 298;
       T   MW 204;
       L   MB 49;
       T   MB 200;
       A   Q 6.7;
       =   M 201.0;
       A   M 2.1;
       =   M 201.1;
       A   I 12.7;
       =   M 201.2;
       A   M 0.0;
       =   M 201.3;
  NETWORK
       CALL FC 15;
  NETWORK
       A   M 201.0;
       =   Q 6.7;
       L   MB 200;
       T   MB 49;
       L   MW 204;
       T   DBW 298;
       L   MW 206;
       T   DBW 98;
  NETWORK
       OPN DB 108;
       L   MB 202;
       T   DBB 58;


END_FUNCTION

FUNCTION FC 69 : VOID
  BEGIN
  NETWORK
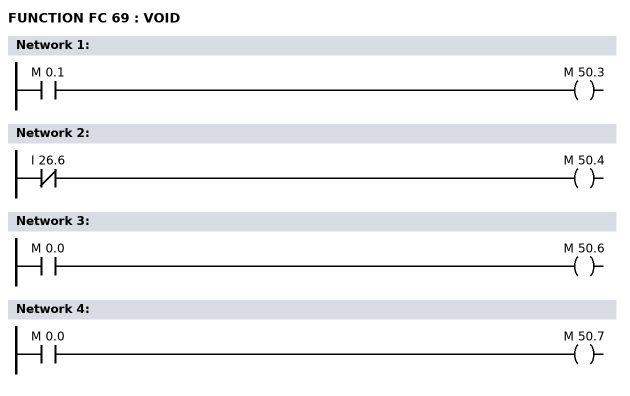
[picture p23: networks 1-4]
       A   M 0.1;
       =   M 50.3;
  NETWORK
       AN  I 26.6;
       =   M 50.4;
  NETWORK
       A   M 0.0;
       =   M 50.6;
  NETWORK
       A   M 0.0;
       =   M 50.7;
  NETWORK
       OPN DB 100;
       L   DBW 100;
       T   MW 206;
       L   DBW 300;
       T   MW 204;
       L   MB 50;
       T   MB 200;
       A   Q 7.0;
       =   M 201.0;
       A   M 2.1;
       =   M 201.1;
       A   I 13.0;
       =   M 201.2;
       A   M 0.0;
       =   M 201.3;
  NETWORK
       CALL FC 15;
  NETWORK
       A   M 201.0;
       =   Q 7.0;
       L   MB 200;
       T   MB 50;
       L   MW 204;
       T   DBW 300;
       L   MW 206;
       T   DBW 100;
  NETWORK
       OPN DB 108;
       L   MB 202;
       T   DBB 61;


END_FUNCTION

FUNCTION FC 70 : VOID
  BEGIN
  NETWORK
       AN  I 15.1;
       =   M 51.3;
  NETWORK
       A   M 0.1;
       =   M 51.4;
  NETWORK
       A   M 0.0;
       =   M 51.6;
  NETWORK
       A   M 0.0;
       =   M 51.7;
  NETWORK
       OPN DB 100;
       L   DBW 102;
       T   MW 206;
       L   DBW 302;
       T   MW 204;
       L   MB 51;
       T   MB 200;
       A   Q 7.1;
       =   M 201.0;
       A   M 2.1;
       =   M 201.1;
       A   I 13.1;
       =   M 201.2;
       A   M 0.0;
       =   M 201.3;
  NETWORK
       CALL FC 15;
  NETWORK
       A   M 201.0;
       =   Q 7.1;
       L   MB 200;
       T   MB 51;
       L   MW 204;
       T   DBW 302;
       L   MW 206;
       T   DBW 102;
  NETWORK
       OPN DB 108;
       L   MB 202;
       T   DBB 60;


END_FUNCTION

FUNCTION FC 71 : VOID
  BEGIN
  NETWORK
       A   M 0.1;
       =   M 52.3;
  NETWORK
       A   M 0.1;
       =   M 52.4;
  NETWORK
       A   M 0.0;
       =   M 52.6;
  NETWORK
       A   M 0.0;
       =   M 52.7;
  NETWORK
       OPN DB 100;
       L   DBW 104;
       T   MW 206;
       L   DBW 304;
       T   MW 204;
       L   MB 52;
       T   MB 200;
       A   Q 7.2;
       =   M 201.0;
       A   M 2.1;
       =   M 201.1;
       A   I 13.2;
       =   M 201.2;
       A   M 0.0;
       =   M 201.3;
  NETWORK
       CALL FC 15;
  NETWORK
       A   M 201.0;
       =   Q 7.2;
       L   MB 200;
       T   MB 52;
       L   MW 204;
       T   DBW 304;
       L   MW 206;
       T   DBW 104;
  NETWORK
       OPN DB 108;
       L   MB 202;
       T   DBB 63;


END_FUNCTION

FUNCTION FC 72 : VOID
  BEGIN
  NETWORK
       A   M 0.1;
       =   M 53.3;
  NETWORK
       AN  I 26.6;
       =   M 53.4;
  NETWORK
       A   M 0.0;
       =   M 53.6;
  NETWORK
       A   M 0.0;
       =   M 53.7;
  NETWORK
       OPN DB 100;
       L   DBW 106;
       T   MW 206;
       L   DBW 306;
       T   MW 204;
       L   MB 53;
       T   MB 200;
       A   Q 7.3;
       =   M 201.0;
       A   M 2.1;
       =   M 201.1;
       A   I 13.3;
       =   M 201.2;
       A   M 0.0;
       =   M 201.3;
  NETWORK
       CALL FC 15;
  NETWORK
       A   M 201.0;
       =   Q 7.3;
       L   MB 200;
       T   MB 53;
       L   MW 204;
       T   DBW 306;
       L   MW 206;
       T   DBW 106;
  NETWORK
       OPN DB 108;
       L   MB 202;
       T   DBB 62;


END_FUNCTION

FUNCTION FC 73 : VOID
  BEGIN
  NETWORK
       ON  I 41.3;
       ON  I 24.3;
       ON  I 24.7;
       O   M 180.5;
       =   M 54.3;
  NETWORK
       AN  I 30.4;
       L   S5TIME#5m;
       SF  T 85;
       NOP 0;
       NOP 0;
       NOP 0;
       A   T 85;
       =   M 54.4;
  NETWORK
       A   M 0.0;
       =   M 54.6;
  NETWORK
       A   M 0.0;
       =   M 54.7;
  NETWORK
       OPN DB 100;
       L   DBW 108;
       T   MW 206;
       L   DBW 308;
       T   MW 204;
       L   MB 54;
       T   MB 200;
       A   Q 10.5;
       =   M 201.0;
       A   M 2.1;
       =   M 201.1;
       A   I 28.0;
       =   M 201.2;
       A   M 0.0;
       =   M 201.3;
  NETWORK
       CALL FC 15;
  NETWORK
       A   M 201.0;
       =   Q 10.5;
       L   MB 200;
       T   MB 54;
       L   MW 204;
       T   DBW 308;
       L   MW 206;
       T   DBW 108;
  NETWORK
       OPN DB 108;
       L   MB 202;
       T   DBB 65;


END_FUNCTION

FUNCTION FC 74 : VOID
  BEGIN
  NETWORK
  TITLE = ;Schredder MA-153
       AN  I 12.6;
       =   M 55.3;
  NETWORK
       A   M 0.1;
       =   M 55.4;
  NETWORK
       A   M 0.0;
       =   M 55.6;
  NETWORK
       A   M 0.0;
       =   M 55.7;
  NETWORK
       OPN DB 100;
       L   DBW 110;
       T   MW 206;
       L   DBW 310;
       T   MW 204;
       L   MB 55;
       T   MB 200;
       A   Q 7.5;
       =   M 201.0;
       A   M 2.1;
       =   M 201.1;
       A   I 13.5;
       =   M 201.2;
       A   M 0.0;
       =   M 201.3;
  NETWORK
       CALL FC 15;
  NETWORK
       A   M 201.0;
       =   Q 7.5;
       L   MB 200;
       T   MB 55;
       L   MW 204;
       T   DBW 310;
       L   MW 206;
       T   DBW 110;
  NETWORK
       OPN DB 108;
       L   MB 202;
       T   DBB 64;


END_FUNCTION

FUNCTION FC 75 : VOID
  BEGIN
  NETWORK
  TITLE = ;MK150
    //STOP VOORWAARDEN
    //
       AN  I 37.0;
       AN  I 15.0;
       O;
       AN  I 13.7;
       AN  I 14.6;
       ON  I 32.6;
       =   M 56.3;
  NETWORK
       A   M 0.1;
       =   M 56.4;
  NETWORK
       A(;
       O   I 37.0;
       O   I 15.0;
       );
       A(;
       O   I 13.7;
       O   I 14.6;
       );
       A   I 4.7;
       =   M 56.6;
  NETWORK
       A   M 0.0;
       =   M 56.7;
  NETWORK
       OPN DB 100;
       L   DBW 112;
       T   MW 206;
       L   DBW 312;
       T   MW 204;
       L   MB 56;
       T   MB 200;
       A   Q 7.6;
       =   M 201.0;
       A   M 2.1;
       =   M 201.1;
       A   I 13.6;
       =   M 201.2;
       A   M 0.0;
       =   M 201.3;
  NETWORK
       CALL FC 15;
  NETWORK
       A   M 201.0;
       =   Q 7.6;
       L   MB 200;
       T   MB 56;
       L   MW 204;
       T   DBW 312;
       L   MW 206;
       T   DBW 112;
  NETWORK
       OPN DB 108;
       L   MB 202;
       T   DBB 67;


END_FUNCTION

FUNCTION FC 76 : VOID
  BEGIN
  NETWORK
  TITLE = ;MK151.1
       O   M 181.3;
       O(;
       AN  I 37.0;
       AN  I 15.0;
       L   DBW 184;
       SD  T 92;
       NOP 0;
       NOP 0;
       NOP 0;
       A   T 92;
       );
       =   M 57.3;
  NETWORK
       A   M 0.1;
       =   M 57.4;
  NETWORK
       AN  M 177.4;
       A(;
       O   I 37.0;
       O   I 15.0;
       );
       O   M 0.0;
       =   M 57.6;
  NETWORK
       A   M 0.0;
       =   M 57.7;
  NETWORK
       OPN DB 100;
       L   DBW 114;
       T   MW 206;
       L   DBW 314;
       T   MW 204;
       L   MB 57;
       T   MB 200;
       A   Q 7.7;
       =   M 201.0;
       A   M 2.1;
       =   M 201.1;
       A   Q 7.7;
       A   I 13.7;
       =   M 201.2;
       A   M 0.0;
       =   M 201.3;
  NETWORK
       CALL FC 15;
  NETWORK
       A   M 201.0;
       =   Q 7.7;
       L   MB 200;
       T   MB 57;
       L   MW 204;
       T   DBW 314;
       L   MW 206;
       T   DBW 114;
  NETWORK
       OPN DB 108;
       L   MB 202;
       T   DBB 66;


END_FUNCTION

FUNCTION FC 77 : VOID
  BEGIN
  NETWORK
       A   M 0.1;
       =   M 58.3;
  NETWORK
       A   M 0.1;
       =   M 58.4;
  NETWORK
       A   M 0.0;
       =   M 58.6;
  NETWORK
       A   M 0.0;
       =   M 58.7;
  NETWORK
       OPN DB 100;
       L   DBW 116;
       T   MW 206;
       L   DBW 316;
       T   MW 204;
       L   MB 58;
       T   MB 200;
       A   Q 8.0;
       =   M 201.0;
       A   M 2.1;
       =   M 201.1;
       A   I 14.0;
       =   M 201.2;
       A   M 0.0;
       =   M 201.3;
  NETWORK
       CALL FC 15;
  NETWORK
       A   M 201.0;
       =   Q 8.0;
       L   MB 200;
       T   MB 58;
       L   MW 204;
       T   DBW 316;
       L   MW 206;
       T   DBW 116;
  NETWORK
       OPN DB 108;
       L   MB 202;
       T   DBB 69;


END_FUNCTION

FUNCTION FC 78 : VOID
  BEGIN
  NETWORK
       A   M 0.1;
       =   M 59.3;
  NETWORK
       //;
       ON  I 40.1;
       =   M 59.4;
  NETWORK
       A   M 0.0;
       =   M 59.6;
  NETWORK
       A   M 0.0;
       =   M 59.7;
  NETWORK
       OPN DB 100;
       L   DBW 118;
       T   MW 206;
       L   DBW 318;
       T   MW 204;
       L   MB 59;
       T   MB 200;
       A   Q 8.1;
       =   M 201.0;
       A   M 2.1;
       =   M 201.1;
       A   I 14.1;
       =   M 201.2;
       A   M 0.0;
       =   M 201.3;
  NETWORK
       CALL FC 15;
  NETWORK
       A   M 201.0;
       =   Q 8.1;
       L   MB 200;
       T   MB 59;
       L   MW 204;
       T   DBW 318;
       L   MW 206;
       T   DBW 118;
  NETWORK
       OPN DB 108;
       L   MB 202;
       T   DBB 68;


END_FUNCTION

FUNCTION FC 79 : VOID
  BEGIN
  NETWORK
  TITLE = ;MA152.1
       A   M 0.1;
       =   M 60.3;
  NETWORK
       A   M 0.1;
       =   M 60.4;
  NETWORK
       A   M 0.0;
       =   M 60.6;
  NETWORK
       A   M 0.0;
       =   M 60.7;
  NETWORK
       OPN DB 100;
       L   DBW 120;
       T   MW 206;
       L   DBW 320;
       T   MW 204;
       L   MB 60;
       T   MB 200;
       A   Q 8.2;
       =   M 201.0;
       A   M 2.1;
       =   M 201.1;
       A   I 14.2;
       =   M 201.2;
       A   M 0.0;
       =   M 201.3;
  NETWORK
       CALL FC 15;
  NETWORK
       A   M 201.0;
       =   Q 8.2;
       L   MB 200;
       T   MB 60;
       L   MW 204;
       T   DBW 320;
       L   MW 206;
       T   DBW 120;
  NETWORK
       OPN DB 108;
       L   MB 202;
       T   DBB 71;


END_FUNCTION

FUNCTION FC 80 : VOID
  BEGIN
  NETWORK
       A   M 0.1;
       =   M 61.1;
  NETWORK
       A   M 0.1;
       =   M 61.2;
  NETWORK
       A   M 0.1;
       =   M 61.3;
  NETWORK
       ON  I 6.7;
       =   M 61.4;
  NETWORK
       A   M 0.0;
       =   M 61.6;
  NETWORK
       A   M 0.0;
       =   M 61.7;
  NETWORK
       OPN DB 100;
       L   DBW 122;
       T   MW 206;
       L   DBW 322;
       T   MW 204;
       L   MB 61;
       T   MB 200;
       A   Q 8.3;
       =   M 201.0;
       A   M 2.1;
       =   M 201.1;
       A   I 14.3;
       =   M 201.2;
       A   M 0.0;
       =   M 201.3;
  NETWORK
       CALL FC 15;
  NETWORK
       A   M 201.0;
       =   Q 8.3;
       L   MB 200;
       T   MB 61;
       L   MW 204;
       T   DBW 322;
       L   MW 206;
       T   DBW 122;
  NETWORK
       OPN DB 108;
       L   MB 202;
       T   DBB 70;


END_FUNCTION

FUNCTION FC 81 : VOID
  BEGIN
  NETWORK
  TITLE = ;MP815.1
       AN  I 43.6;
       =   M 62.3;
  NETWORK
       A   M 0.1;
       =   M 62.4;
  NETWORK
       AN  I 40.2;
       S   M 106.5;
       AN  M 179.6;
       S   M 106.6;
       AN  I 38.1;
       S   M 106.7;
       A   M 180.4;
       S   M 107.0;
       AN  I 39.3;
       S   M 107.1;
       //;
       AN  M 106.5;
       AN  M 106.6;
       AN  M 106.7;
       AN  M 107.0;
       AN  M 107.1;
       O   M 0.0;
       =   M 62.6;
  NETWORK
       A   M 0.0;
       =   M 62.7;
  NETWORK
       OPN DB 100;
       L   DBW 124;
       T   MW 206;
       L   DBW 324;
       T   MW 204;
       L   MB 62;
       T   MB 200;
       A   Q 10.6;
       =   M 201.0;
       A   M 2.1;
       =   M 201.1;
       A   I 28.1;
       =   M 201.2;
       A   M 0.0;
       =   M 201.3;
  NETWORK
       CALL FC 15;
  NETWORK
       A   M 201.0;
       =   Q 10.6;
       L   MB 200;
       T   MB 62;
       L   MW 204;
       T   DBW 324;
       L   MW 206;
       T   DBW 124;
  NETWORK
       OPN DB 108;
       L   MB 202;
       T   DBB 73;


END_FUNCTION

FUNCTION FC 82 : VOID
  BEGIN
  NETWORK
  TITLE = ;
       A   M 0.1;
       =   M 63.3;
  NETWORK
       A   M 0.1;
       =   M 63.4;
  NETWORK
       A   M 0.0;
       =   M 63.6;
  NETWORK
       A   M 0.0;
       =   M 63.7;
  NETWORK
       OPN DB 100;
       L   DBW 126;
       T   MW 206;
       L   DBW 326;
       T   MW 204;
       L   MB 63;
       T   MB 200;
       A   Q 8.5;
       =   M 201.0;
       A   M 2.1;
       =   M 201.1;
       A   I 14.5;
       =   M 201.2;
       A   M 0.0;
       =   M 201.3;
  NETWORK
       CALL FC 15;
  NETWORK
       A   M 201.0;
       =   Q 8.5;
       L   MB 200;
       T   MB 63;
       L   MW 204;
       T   DBW 326;
       L   MW 206;
       T   DBW 126;
  NETWORK
       OPN DB 108;
       L   MB 202;
       T   DBB 72;


END_FUNCTION

FUNCTION FC 83 : VOID
  BEGIN
  NETWORK
  TITLE = ;MK151.2
       O   M 181.3;
       O   T 92;
       =   M 64.3;
  NETWORK
       A   M 0.1;
       =   M 64.4;
  NETWORK
       AN  M 177.4;
       A(;
       O   I 37.0;
       O   I 15.0;
       );
       O   M 0.0;
       =   M 64.6;
  NETWORK
       A   M 0.0;
       =   M 64.7;
  NETWORK
       OPN DB 100;
       L   DBW 128;
       T   MW 206;
       L   DBW 328;
       T   MW 204;
       L   MB 64;
       T   MB 200;
       A   Q 8.6;
       =   M 201.0;
       A   M 2.1;
       =   M 201.1;
       A   Q 8.6;
       A   I 14.6;
       =   M 201.2;
       A   M 0.0;
       =   M 201.3;
  NETWORK
       CALL FC 15;
  NETWORK
       A   M 201.0;
       =   Q 8.6;
       =   M 190.3;
       L   MB 200;
       T   MB 64;
       L   MW 204;
       T   DBW 328;
       L   MW 206;
       T   DBW 128;
  NETWORK
       OPN DB 108;
       L   MB 202;
       T   DBB 75;


END_FUNCTION

FUNCTION FC 84 : VOID
  BEGIN
  NETWORK
  TITLE = ;MP815.2
       AN  I 43.6;
       =   M 65.3;
  NETWORK
       A   M 0.1;
       =   M 65.4;
  NETWORK
       A   M 0.0;
       =   M 65.6;
  NETWORK
       A   M 0.0;
       =   M 65.7;
  NETWORK
       OPN DB 100;
       L   DBW 130;
       T   MW 206;
       L   DBW 330;
       T   MW 204;
       L   MB 65;
       T   MB 200;
       A   Q 8.7;
       =   M 201.0;
       A   M 2.1;
       =   M 201.1;
       A   I 14.7;
       =   M 201.2;
       A   M 0.0;
       =   M 201.3;
  NETWORK
       CALL FC 15;
  NETWORK
       A   M 201.0;
       =   Q 8.7;
       L   MB 200;
       T   MB 65;
       L   MW 204;
       T   DBW 330;
       L   MW 206;
       T   DBW 130;
  NETWORK
       OPN DB 108;
       L   MB 202;
       T   DBB 74;


END_FUNCTION

FUNCTION FC 85 : VOID
  BEGIN
  NETWORK
  TITLE = ;MK818.2
       O   T 60;
       O;
       A   M 0.1;
       AN  M 180.6;
       AN  M 180.7;
       AN  M 181.0;
       O   M 103.3;
       O;
       A   T 6;
       AN  M 106.5;
       AN  M 106.6;
       O;
       AN  I 14.7;
       AN  I 28.1;
       =   M 66.3;
  NETWORK
       A   M 0.1;
       =   M 66.4;
  NETWORK
       A(;
       O   I 28.1;
       O   I 14.7;
       );
       AN  M 178.6;
       =   M 66.6;
  NETWORK
       A   M 0.0;
       =   M 66.7;
  NETWORK
       OPN DB 100;
       L   DBW 132;
       T   MW 206;
       L   DBW 332;
       T   MW 204;
       L   MB 66;
       T   MB 200;
       A   Q 9.0;
       =   M 201.0;
       A   M 2.1;
       =   M 201.1;
       A   I 15.0;
       =   M 201.2;
       A   M 0.0;
       =   M 201.3;
  NETWORK
       A   M 178.6;
       AN  M 190.2;
       =   M 190.2;
       A   M 190.2;
       JCN   X000;
     CALL FC 8;
  X000: NOP 0;
  NETWORK
       CALL FC 15;
  NETWORK
       A   M 201.0;
       =   Q 9.0;
       =   M 190.1;
       L   MB 200;
       T   MB 66;
       L   MW 204;
       T   DBW 332;
       L   MW 206;
       T   DBW 132;
  NETWORK
       OPN DB 108;
       L   MB 202;
       T   DBB 77;


END_FUNCTION

FUNCTION FC 86 : VOID
  BEGIN
  NETWORK
       OPN DB 100;
       O   DBX 121.3;
       O   M 101.4;
       O   M 60.5;
       =   M 68.3;
  NETWORK
       OPN DB 94;
       AN  I 14.2;
       L   DBW 164;
       SF  T 82;
       NOP 0;
       NOP 0;
       NOP 0;
       //;
       O   T 82;
       ON  I 0.6;
       O   I 0.2;
       =   M 68.4;
  NETWORK
       A   M 0.0;
       =   M 68.6;
  NETWORK
       A   M 0.0;
       =   M 68.7;
  NETWORK
       OPN DB 100;
       L   DBW 136;
       T   MW 206;
       L   DBW 336;
       T   MW 204;
       L   MB 68;
       T   MB 200;
       A   Q 9.3;
       =   M 201.0;
       A   M 2.1;
       =   M 201.1;
       A   I 15.7;
       =   M 201.2;
       A   M 0.0;
       =   M 201.3;
  NETWORK
       CALL FC 15;
  NETWORK
       A   M 201.0;
       =   Q 9.3;
       L   MB 200;
       T   MB 68;
       L   MW 204;
       T   DBW 336;
       L   MW 206;
       T   DBW 136;
  NETWORK
       OPN DB 108;
       L   MB 202;
       T   DBB 79;


END_FUNCTION

FUNCTION FC 87 : VOID
  BEGIN
  NETWORK
       A   M 0.1;
       =   M 184.7;
       OPN DB 181;
       L   DBW 238;
       L   1;
       <I;
       S   M 184.7;
  NETWORK
       O   I 31.7;
       ON  I 32.2;
       O   M 184.0;
       O   M 184.2;
       ON  M 175.4;
       =   M 69.3;
  NETWORK
       A   M 0.1;
       =   M 69.4;
  NETWORK
       A   M 103.0;
       AN  I 31.7;
       A   M 184.7;
       =   M 69.6;
  NETWORK
       OPN DB 100;
       L   DBW 138;
       T   MW 206;
  NETWORK
       O   M 69.6;
       O   M 206.3;
       S   Q 12.5;
  NETWORK
       A(;
       O   M 69.3;
       O   I 31.5;
       );
       AN  M 206.3;
       R   Q 12.5;
  NETWORK
       A   I 31.5;
       =   M 207.3;
  NETWORK
       A   M 2.0;
       S   M 206.6;
       AN  M 207.3;
       R   M 206.6;
  NETWORK
       AN  I 31.6;
       =   M 202.0;
       =   M 202.1;
  NETWORK
       A   M 207.3;
       S   M 202.0;
       R   M 202.1;
  NETWORK
       A   M 206.6;
       R   M 202.0;
       S   M 202.1;
  NETWORK
       L   MW 206;
       T   DBW 138;
  NETWORK
       OPN DB 108;
       L   MB 202;
       T   DBB 78;


END_FUNCTION

FUNCTION FC 88 : VOID
  BEGIN
  NETWORK
       ON  I 25.6;
       ON  I 25.1;
       =   M 70.3;
  NETWORK
       A   M 0.1;
       =   M 70.4;
  NETWORK
       A   M 0.0;
       =   M 70.6;
  NETWORK
       A   M 0.0;
       =   M 70.7;
  NETWORK
       OPN DB 100;
       L   DBW 140;
       T   MW 206;
       L   DBW 340;
       T   MW 204;
       L   MB 70;
       T   MB 200;
  NETWORK
       O   M 0.0;
       =   M 206.0;
  NETWORK
       A   Q 11.0;
       =   M 201.0;
       A   M 2.1;
       =   M 201.1;
       A   I 28.7;
       =   M 201.2;
       A   M 0.0;
       =   M 201.3;
  NETWORK
       CALL FC 15;
  NETWORK
       A   M 201.0;
       =   Q 11.0;
       L   MB 200;
       T   MB 70;
       L   MW 204;
       T   DBW 340;
       L   MW 206;
       T   DBW 140;
  NETWORK
       OPN DB 108;
       L   MB 202;
       T   DBB 81;


END_FUNCTION

FUNCTION FC 89 : VOID
  BEGIN
  NETWORK
       ON  I 25.6;
       ON  I 25.2;
       =   M 71.3;
  NETWORK
       A   M 0.1;
       =   M 71.4;
  NETWORK
       A   M 0.0;
       =   M 71.6;
  NETWORK
       A   M 0.0;
       =   M 71.7;
  NETWORK
       OPN DB 100;
       L   DBW 142;
       T   MW 206;
       L   DBW 342;
       T   MW 204;
       L   MB 71;
       T   MB 200;
  NETWORK
       O   M 0.0;
       =   M 206.0;
  NETWORK
       A   Q 11.1;
       =   M 201.0;
       A   M 2.1;
       =   M 201.1;
       A   I 30.0;
       =   M 201.2;
       A   M 0.0;
       =   M 201.3;
  NETWORK
       CALL FC 15;
  NETWORK
       A   M 201.0;
       =   Q 11.1;
       L   MB 200;
       T   MB 71;
       L   MW 204;
       T   DBW 342;
       L   MW 206;
       T   DBW 142;
  NETWORK
       OPN DB 108;
       L   MB 202;
       T   DBB 80;


END_FUNCTION

FUNCTION FC 90 : VOID
  BEGIN
  NETWORK
       OPN DB 94;
  NETWORK
       A   M 0.1;
       =   M 72.3;
  NETWORK
       A   M 0.1;
       =   M 72.4;
  NETWORK
       O   Q 13.6;
       ON  Q 13.7;
       L   DBW 202;
       SE  T 101;
       NOP 0;
       NOP 0;
       NOP 0;
       NOP 0;
  NETWORK
       AN  T 101;
       =   M 72.6;
       =   M 72.7;
  NETWORK
       OPN DB 100;
       L   DBW 144;
       T   MW 206;
       L   DBW 344;
       T   MW 204;
       L   MB 72;
       T   MB 200;
       A   M 200.0;
       =   M 201.0;
       AN  I 34.7;
       =   M 201.1;
       A   M 200.0;
       =   M 201.2;
       A   M 0.0;
       =   M 201.3;
  NETWORK
       CALL FC 15;
  NETWORK
       OPN DB 94;
       L   DBW 198;
       A   M 201.0;
       SP  T 99;
       A   T 99;
       =   Q 13.6;
       L   DBW 200;
       AN  M 201.0;
       SP  T 100;
       AN  T 100;
       =   Q 13.7;
       //;
       OPN DB 100;
       L   MB 200;
       T   MB 72;
       L   MW 204;
       T   DBW 344;
       L   MW 206;
       T   DBW 144;
  NETWORK
       OPN DB 108;
       L   MB 202;
       T   DBB 83;


END_FUNCTION

FUNCTION FC 91 : VOID
  BEGIN
  NETWORK
       OPN DB 94;
  NETWORK
       A   M 0.1;
       =   M 73.3;
  NETWORK
       A   M 0.1;
       =   M 73.4;
  NETWORK
       O   Q 14.1;
       ON  Q 14.2;
       L   DBW 214;
       SE  T 107;
       NOP 0;
       NOP 0;
       NOP 0;
       NOP 0;
  NETWORK
       AN  T 107;
       =   M 73.6;
       =   M 73.7;
  NETWORK
       OPN DB 100;
       L   DBW 146;
       T   MW 206;
       L   DBW 346;
       T   MW 204;
       L   MB 73;
       T   MB 200;
       A   M 200.0;
       =   M 201.0;
       AN  I 36.3;
       =   M 201.1;
       A   M 200.0;
       =   M 201.2;
       A   M 0.0;
       =   M 201.3;
  NETWORK
       CALL FC 15;
  NETWORK
       OPN DB 94;
       L   DBW 210;
       A   M 201.0;
       SP  T 105;
       A   T 105;
       =   Q 14.1;
       L   DBW 212;
       AN  M 201.0;
       SP  T 106;
       AN  T 106;
       =   Q 14.2;
       //;
       OPN DB 100;
       L   MB 200;
       T   MB 73;
       L   MW 204;
       T   DBW 346;
       L   MW 206;
       T   DBW 146;
  NETWORK
       OPN DB 108;
       L   MB 202;
       T   DBB 82;


END_FUNCTION

FUNCTION FC 92 : VOID
  BEGIN
  NETWORK
       AN  M 181.4;
       =   M 75.3;
  NETWORK
       A   M 0.1;
       =   M 75.4;
  NETWORK
       A   M 0.0;
       =   M 75.6;
  NETWORK
       A   M 0.0;
       =   M 75.7;
  NETWORK
       OPN DB 100;
       L   DBW 150;
       T   MW 206;
       L   DBW 350;
       T   MW 204;
       L   MB 75;
       T   MB 200;
       A   Q 5.1;
       =   M 201.0;
       A   M 2.1;
       =   M 201.1;
       A   I 5.6;
       =   M 201.2;
       A   M 0.0;
       =   M 201.3;
  NETWORK
       CALL FC 15;
  NETWORK
       A   M 201.0;
       =   Q 5.1;
       L   MB 200;
       T   MB 75;
       L   MW 204;
       T   DBW 350;
       L   MW 206;
       T   DBW 150;
  NETWORK
       OPN DB 108;
       L   MB 202;
       T   DBB 84;


END_FUNCTION

FUNCTION FC 93 : VOID
  BEGIN
  NETWORK
       //;
       O(;
       AN  I 28.7;
       AN  I 30.0;
       AN  I 36.5;
       );
       O(;
       AN  I 45.5;
       L   DBW 44;
       SD  T 22;
       NOP 0;
       NOP 0;
       NOP 0;
       A   T 22;
       );
       =   M 77.3;
  NETWORK
       A   M 0.1;
       =   M 77.4;
  NETWORK
       A   M 0.0;
       =   M 77.6;
  NETWORK
       A   M 0.0;
       =   M 77.7;
  NETWORK
       OPN DB 100;
       L   DBW 154;
       T   MW 206;
       L   DBW 354;
       T   MW 204;
       L   MB 77;
       T   MB 200;
       A   Q 5.3;
       =   M 201.0;
       A   M 2.1;
       =   M 201.1;
       A   I 28.2;
       =   M 201.2;
       A   M 0.0;
       =   M 201.3;
  NETWORK
       CALL FC 15;
  NETWORK
       A   M 201.0;
       =   Q 5.3;
       L   MB 200;
       T   MB 77;
       L   MW 204;
       T   DBW 354;
       L   MW 206;
       T   DBW 154;
  NETWORK
       OPN DB 108;
       L   MB 202;
       T   DBB 86;
  NETWORK
       OPN DB 94;
  NETWORK
       A   Q 5.3;
       L   DBW 78;
       SP  T 39;
       NOP 0;
       NOP 0;
       NOP 0;
       A   T 39;
       =   Q 0.1;
       //;


END_FUNCTION

FUNCTION FC 94 : VOID
  BEGIN
  NETWORK
       //;
       ON  I 3.6;
       =   M 78.3;
  NETWORK
       A   M 0.1;
       =   M 78.4;
  NETWORK
       A   M 0.0;
       =   M 78.6;
  NETWORK
       A   M 0.0;
       =   M 78.7;
  NETWORK
       OPN DB 100;
       L   DBW 156;
       T   MW 206;
       L   DBW 356;
       T   MW 204;
       L   MB 78;
       T   MB 200;
       A   Q 5.4;
       =   M 201.0;
       A   M 2.1;
       =   M 201.1;
       A   I 37.6;
       =   M 201.2;
       A   M 0.0;
       =   M 201.3;
  NETWORK
       CALL FC 15;
  NETWORK
       A   M 201.0;
       =   Q 5.4;
       L   MB 200;
       T   MB 78;
       L   MW 204;
       T   DBW 356;
       L   MW 206;
       T   DBW 156;
  NETWORK
       OPN DB 108;
       L   MB 202;
       T   DBB 89;


END_FUNCTION

FUNCTION FC 95 : VOID
  BEGIN
  NETWORK
       //;
       ON  I 3.6;
       =   M 79.3;
  NETWORK
       A   M 0.1;
       =   M 79.4;
  NETWORK
       A   M 0.0;
       =   M 79.6;
  NETWORK
       A   M 0.0;
       =   M 79.7;
  NETWORK
       OPN DB 100;
       L   DBW 158;
       T   MW 206;
       L   DBW 358;
       T   MW 204;
       L   MB 79;
       T   MB 200;
       A   Q 5.5;
       =   M 201.0;
       A   M 2.1;
       =   M 201.1;
       A   I 37.7;
       =   M 201.2;
       A   M 0.0;
       =   M 201.3;
  NETWORK
       CALL FC 15;
  NETWORK
       A   M 201.0;
       =   Q 5.5;
       L   MB 200;
       T   MB 79;
       L   MW 204;
       T   DBW 358;
       L   MW 206;
       T   DBW 158;
  NETWORK
       OPN DB 108;
       L   MB 202;
       T   DBB 88;


END_FUNCTION

FUNCTION FC 96 : VOID
  AUTHOR: _30084
  BEGIN
  NETWORK


END_FUNCTION

FUNCTION FC 97 : VOID
  BEGIN
  NETWORK
       O   I 46.0;
       ON  M 173.7;
       =   M 81.3;
  NETWORK
       A   M 0.1;
       =   M 81.4;
  NETWORK
       A   M 0.0;
       =   M 81.6;
  NETWORK
       A   M 0.0;
       =   M 81.7;
  NETWORK
       OPN DB 100;
       L   DBW 162;
       T   MW 206;
       L   DBW 362;
       T   MW 204;
       L   MB 81;
       T   MB 200;
       A   Q 5.7;
       =   M 201.0;
       A   M 2.1;
       =   M 201.1;
       A   I 14.4;
       =   M 201.2;
       A   M 0.0;
       =   M 201.3;
  NETWORK
       CALL FC 15;
  NETWORK
       A   M 201.0;
       =   Q 5.7;
       L   MB 200;
       T   MB 81;
       L   MW 204;
       T   DBW 362;
       L   MW 206;
       T   DBW 162;
  NETWORK
       OPN DB 108;
       L   MB 202;
       T   DBB 90;


END_FUNCTION

FUNCTION FC 98 : VOID
  BEGIN
  NETWORK
       ON  I 41.3;
       ON  I 25.6;
       ON  I 25.3;
       =   M 82.3;
  NETWORK
       A   M 0.1;
       =   M 82.4;
  NETWORK
       A   M 0.0;
       =   M 82.6;
  NETWORK
       A   M 0.0;
       =   M 82.7;
  NETWORK
       OPN DB 100;
       L   DBW 164;
       T   MW 206;
       L   DBW 364;
       T   MW 204;
       L   MB 82;
       T   MB 200;
  NETWORK
       O   M 0.0;
       =   M 206.0;
  NETWORK
       A   Q 11.5;
       =   M 201.0;
       A   M 2.1;
       =   M 201.1;
       A   I 36.5;
       =   M 201.2;
       A   M 0.0;
       =   M 201.3;
  NETWORK
       CALL FC 15;
  NETWORK
       A   M 201.0;
       =   Q 11.5;
       L   MB 200;
       T   MB 82;
       L   MW 204;
       T   DBW 364;
       L   MW 206;
       T   DBW 164;
  NETWORK
       OPN DB 108;
       L   MB 202;
       T   DBB 93;


END_FUNCTION

FUNCTION FC 99 : VOID
  BEGIN
  NETWORK
  TITLE = MK818.1
       OPN DB 94;
       AN  I 28.7;
       AN  I 30.0;
       AN  I 36.5;
       S   M 103.3;
       A   M 103.0;
       A   M 103.1;
       R   M 103.3;
       O   I 28.7;
       O   I 30.0;
       O   I 36.5;
       R   M 103.3;
  NETWORK
       O(;
       A   M 180.0;
       L   DBW 120;
       SD  T 60;
       NOP 0;
       NOP 0;
       NOP 0;
       A   T 60;
       );
       O;
       AN  M 180.6;
       AN  M 180.7;
       AN  M 181.0;
       A   M 0.1;
       O   M 103.3;
       O;
       A(;
       A   M 180.1;
       L   S5TIME#2m;
       SD  T 6;
       NOP 0;
       NOP 0;
       NOP 0;
       A   T 6;
       );
       AN  M 106.5;
       AN  M 106.6;
       O;
       AN  I 14.7;
       AN  I 28.1;
       =   M 83.3;
  NETWORK
       A   M 0.1;
       =   M 83.4;
  NETWORK
       A(;
       O   I 14.7;
       O   I 28.1;
       );
       AN  M 178.6;
       =   M 83.6;
  NETWORK
       A   M 0.0;
       =   M 83.7;
  NETWORK
       OPN DB 100;
       L   DBW 166;
       T   MW 206;
       L   DBW 366;
       T   MW 204;
       L   MB 83;
       T   MB 200;
       A   Q 14.3;
       =   M 201.0;
       A   M 2.1;
       =   M 201.1;
       A   I 37.0;
       =   M 201.2;
       A   M 0.0;
       =   M 201.3;
  NETWORK
       A   M 178.6;
       AN  M 190.0;
       =   M 190.0;
       A   M 190.0;
       JCN   X000;
     CALL FC 8;
  X000: NOP 0;
  NETWORK
       CALL FC 15;
  NETWORK
       A   M 201.0;
       =   Q 14.3;
       L   MB 200;
       T   MB 83;
       L   MW 204;
       T   DBW 366;
       L   MW 206;
       T   DBW 166;
  NETWORK
       OPN DB 108;
       L   MB 202;
       T   DBB 92;


END_FUNCTION

FUNCTION FC 100 : VOID
  BEGIN
  NETWORK
       AN  I 41.3;
       =   M 84.3;
  NETWORK
       OPN DB 94;
       //;
       AN  I 25.5;
       L   DBW 54;
       SD  T 27;
       NOP 0;
       NOP 0;
       NOP 0;
       A   T 27;
       =   M 84.4;
  NETWORK
       A   M 0.0;
       =   M 84.6;
  NETWORK
       A   M 0.0;
       =   M 84.7;
  NETWORK
       OPN DB 100;
       L   DBW 168;
       T   MW 206;
       L   DBW 368;
       T   MW 204;
       L   MB 84;
       T   MB 200;
       A   Q 14.4;
       =   M 201.0;
       A   M 2.1;
       =   M 201.1;
       A   I 37.1;
       =   M 201.2;
       A   M 0.0;
       =   M 201.3;
  NETWORK
       CALL FC 15;
  NETWORK
       A   M 201.0;
       =   Q 14.4;
       L   MB 200;
       T   MB 84;
       L   MW 204;
       T   DBW 368;
       L   MW 206;
       T   DBW 168;
  NETWORK
       OPN DB 108;
       L   MB 202;
       T   DBB 95;


END_FUNCTION

FUNCTION FC 101 : VOID
  BEGIN
  NETWORK
       //;
       O(;
       AN  I 28.7;
       AN  I 30.0;
       AN  I 36.5;
       );
       ON  I 38.4;
       ON  I 41.3;
       =   M 85.3;
  NETWORK
       A   M 0.1;
       =   M 85.4;
  NETWORK
       A   M 0.0;
       =   M 85.6;
  NETWORK
       A   M 0.0;
       =   M 85.7;
  NETWORK
       OPN DB 100;
       L   DBW 170;
       T   MW 206;
       L   DBW 370;
       T   MW 204;
       L   MB 85;
       T   MB 200;
       A   Q 14.5;
       =   M 201.0;
       A   M 2.1;
       =   M 201.1;
       A   I 37.2;
       =   M 201.2;
       A   M 0.0;
       =   M 201.3;
  NETWORK
       CALL FC 15;
  NETWORK
       A   M 201.0;
       =   Q 14.5;
       L   MB 200;
       T   MB 85;
       L   MW 204;
       T   DBW 370;
       L   MW 206;
       T   DBW 170;
  NETWORK
       OPN DB 108;
       L   MB 202;
       T   DBB 94;


END_FUNCTION

FUNCTION FC 102 : VOID
  BEGIN
  NETWORK
       //;
       O(;
       AN  I 28.7;
       AN  I 30.0;
       AN  I 36.5;
       );
       O(;
       AN  I 45.4;
       L   DBW 42;
       SD  T 21;
       NOP 0;
       NOP 0;
       NOP 0;
       A   T 21;
       );
       =   M 86.3;
  NETWORK
       A   M 0.1;
       =   M 86.4;
  NETWORK
       A   M 0.0;
       =   M 86.6;
  NETWORK
       A   M 0.0;
       =   M 86.7;
  NETWORK
       OPN DB 100;
       L   DBW 172;
       T   MW 206;
       L   DBW 372;
       T   MW 204;
       L   MB 86;
       T   MB 200;
       A   Q 14.6;
       =   M 201.0;
       A   M 2.1;
       =   M 201.1;
       A   I 37.3;
       =   M 201.2;
       A   M 0.0;
       =   M 201.3;
  NETWORK
       CALL FC 15;
  NETWORK
       A   M 201.0;
       =   Q 14.6;
       L   MB 200;
       T   MB 86;
       L   MW 204;
       T   DBW 372;
       L   MW 206;
       T   DBW 172;
  NETWORK
       OPN DB 108;
       L   MB 202;
       T   DBB 97;
  NETWORK
       OPN DB 94;
  NETWORK
       A   Q 14.6;
       L   DBW 76;
       SP  T 38;
       NOP 0;
       NOP 0;
       NOP 0;
       A   T 38;
       =   Q 0.0;


END_FUNCTION

FUNCTION FC 103 : VOID
  BEGIN
  NETWORK
       ON  I 14.2;
       =   M 87.3;
  NETWORK
       A   M 0.1;
       =   M 87.4;
  NETWORK
       A   M 0.0;
       =   M 87.6;
  NETWORK
       A   M 0.0;
       =   M 87.7;
  NETWORK
       OPN DB 100;
       L   DBW 174;
       T   MW 206;
       L   DBW 374;
       T   MW 204;
       L   MB 87;
       T   MB 200;
  NETWORK
       A   Q 15.1;
       =   M 201.0;
       A   M 2.1;
       =   M 201.1;
       A   I 3.7;
       =   M 201.2;
       A   M 0.0;
       =   M 201.3;
  NETWORK
       CALL FC 15;
  NETWORK
       A   M 201.0;
       =   Q 15.1;
       L   MB 200;
       T   MB 87;
       L   MW 204;
       T   DBW 374;
       L   MW 206;
       T   DBW 174;
  NETWORK
       OPN DB 108;
       L   MB 202;
       T   DBB 96;


END_FUNCTION

FUNCTION FC 104 : VOID
  BEGIN
  NETWORK
       AN  I 12.5;
       =   M 88.3;
  NETWORK
       A   M 0.1;
       =   M 88.4;
  NETWORK
       A   M 0.0;
       =   M 88.6;
  NETWORK
       A   M 0.0;
       =   M 88.7;
  NETWORK
       OPN DB 100;
       L   DBW 176;
       T   MW 206;
       L   DBW 376;
       T   MW 204;
       L   MB 88;
       T   MB 200;
  NETWORK
       A   Q 15.2;
       =   M 201.0;
       A   M 2.1;
       =   M 201.1;
       A   I 4.0;
       =   M 201.2;
       A   M 0.0;
       =   M 201.3;
  NETWORK
       CALL FC 15;
  NETWORK
       A   M 201.0;
       =   Q 15.2;
       L   MB 200;
       T   MB 88;
       L   MW 204;
       T   DBW 376;
       L   MW 206;
       T   DBW 176;
  NETWORK
       OPN DB 108;
       L   MB 202;
       T   DBB 99;


END_FUNCTION

FUNCTION FC 105 : VOID
  BEGIN
  NETWORK
       O   M 81.3;
       O(;
       A   I 31.7;
       AN  M 184.2;
       );
       O   T 7;
       =   M 89.3;
  NETWORK
       A   M 0.1;
       =   M 89.4;
  NETWORK
       A   M 0.0;
       =   M 89.6;
  NETWORK
       A   M 0.0;
       =   M 89.7;
  NETWORK
       OPN DB 100;
       L   DBW 178;
       T   MW 206;
       L   DBW 378;
       T   MW 204;
       L   MB 89;
       T   MB 200;
       A   Q 10.3;
       =   M 201.0;
       A   M 2.1;
       =   M 201.1;
       A   I 27.6;
       =   M 201.2;
       A   M 0.0;
       =   M 201.3;
  NETWORK
       CALL FC 15;
  NETWORK
       A   M 201.0;
       =   Q 10.3;
       L   MB 200;
       T   MB 89;
       L   MW 204;
       T   DBW 378;
       L   MW 206;
       T   DBW 178;
  NETWORK
       OPN DB 108;
       L   MB 202;
       T   DBB 57;


END_FUNCTION

FUNCTION FC 106 : VOID
  BEGIN
  NETWORK
       A   M 0.1;
       =   M 113.3;
  NETWORK
       A   M 0.0;
       =   M 113.6;
  NETWORK
       A   M 0.0;
       =   M 113.7;
  NETWORK
       OPN DB 110;
       L   DBW 26;
       T   MW 206;
       L   DBW 226;
       T   MW 204;
       L   MB 113;
       T   MB 200;
       A   I 4.3;
       =   M 201.1;
       A   I 5.3;
       =   M 201.2;
  NETWORK
       CALL FC 16;
  NETWORK
       A   M 201.0;
       =   Q 4.3;
       L   MB 200;
       T   MB 113;
       L   MW 204;
       T   DBW 226;
       L   MW 206;
       T   DBW 26;
  NETWORK


END_FUNCTION

FUNCTION FC 107 : VOID
  BEGIN
  NETWORK
       A   M 0.1;
       =   M 114.3;
  NETWORK
       A   M 0.0;
       =   M 114.6;
  NETWORK
       A   M 0.0;
       =   M 114.7;
  NETWORK
       OPN DB 110;
       L   DBW 28;
       T   MW 206;
       L   DBW 228;
       T   MW 204;
       L   MB 114;
       T   MB 200;
       OPN DB 94;
       L   DBW 154;
       AN  I 4.4;
       SD  T 77;
       A   T 77;
       =   M 201.1;
       L   DBW 156;
       AN  I 5.4;
       SD  T 78;
       A   T 78;
       =   M 201.2;
       OPN DB 110;
  NETWORK
       CALL FC 16;
  NETWORK
       A   M 201.0;
       =   Q 4.4;
       L   MB 200;
       T   MB 114;
       L   MW 204;
       T   DBW 228;
       L   MW 206;
       T   DBW 28;
  NETWORK
       OPN DB 118;
       L   MB 202;
       T   DBB 25;


END_FUNCTION

FUNCTION FC 108 : VOID
  BEGIN
  NETWORK
       A   M 0.1;
       =   M 115.3;
  NETWORK
       A   M 0.0;
       =   M 115.6;
  NETWORK
       A   M 0.0;
       =   M 115.7;
  NETWORK
       OPN DB 110;
       L   DBW 30;
       T   MW 206;
       L   DBW 230;
       T   MW 204;
       L   MB 115;
       T   MB 200;
       OPN DB 94;
       L   DBW 158;
       AN  I 4.5;
       SD  T 79;
       A   T 79;
       =   M 201.1;
       L   DBW 160;
       AN  I 5.5;
       SD  T 80;
       A   T 80;
       =   M 201.2;
       OPN DB 110;
  NETWORK
       CALL FC 16;
  NETWORK
       A   M 201.0;
       =   Q 4.5;
       L   MB 200;
       T   MB 115;
       L   MW 204;
       T   DBW 230;
       L   MW 206;
       T   DBW 30;
  NETWORK
       OPN DB 118;
       L   MB 202;
       T   DBB 24;


END_FUNCTION

FUNCTION FC 109 : VOID
  BEGIN
  NETWORK
       A   M 0.1;
       =   M 116.3;
  NETWORK
       A   M 0.0;
       =   M 116.6;
  NETWORK
       A   M 0.0;
       =   M 116.7;
  NETWORK
       OPN DB 110;
       L   DBW 32;
       T   MW 206;
       L   DBW 232;
       T   MW 204;
       L   MB 116;
       T   MB 200;
       AN  Q 15.0;
       =   M 201.1;
       A   Q 15.0;
       =   M 201.2;
  NETWORK
       CALL FC 17;
  NETWORK
       A   M 201.0;
       =   Q 15.0;
       L   MB 200;
       T   MB 116;
       L   MW 204;
       T   DBW 232;
       L   MW 206;
       T   DBW 32;
  NETWORK


END_FUNCTION

FUNCTION FC 110 : VOID
  BEGIN
  NETWORK
       A   M 0.1;
       =   M 117.1;
  NETWORK
       A   M 0.1;
       =   M 117.2;
  NETWORK
       O   M 184.2;
       ON  I 27.6;
       =   M 117.3;
  NETWORK
       A   I 27.6;
       =   M 117.6;
  NETWORK
       A   M 0.0;
       =   M 117.7;
  NETWORK
       OPN DB 110;
       L   DBW 34;
       T   MW 206;
       L   DBW 234;
       T   MW 204;
       L   MB 117;
       T   MB 200;
       AN  I 31.7;
       AN  I 32.0;
       =   M 201.1;
       A   I 31.7;
       AN  I 32.0;
       =   M 201.2;
  NETWORK
       CALL FC 16;
  NETWORK
       OPN DB 110;
       A   M 201.0;
       =   Q 12.6;
       L   MB 200;
       T   MB 117;
       L   MW 204;
       T   DBW 234;
       L   MW 206;
       T   DBW 34;
  NETWORK
       OPN DB 118;
       L   MB 202;
       T   DBB 26;
       //;


END_FUNCTION

FUNCTION FC 111 : VOID
  BEGIN
  NETWORK
       A   M 0.1;
       =   M 118.3;
  NETWORK
       A   M 0.0;
       =   M 118.6;
  NETWORK
       A   M 0.0;
       =   M 118.7;
  NETWORK
       OPN DB 110;
       L   DBW 36;
       T   MW 206;
       L   DBW 236;
       T   MW 204;
       L   MB 118;
       T   MB 200;
       A   I 11.7;
       =   M 201.1;
       A   I 11.6;
       =   M 201.2;
  NETWORK
       CALL FC 16;
  NETWORK
       OPN DB 110;
       A   M 201.0;
       =   Q 19.5;
       AN  Q 19.5;
       =   Q 19.4;
       L   MB 200;
       T   MB 118;
       L   MW 204;
       T   DBW 236;
       L   MW 206;
       T   DBW 36;
  NETWORK
       OPN DB 118;
       L   MB 202;
       T   DBB 29;
       //;


END_FUNCTION

FUNCTION FC 112 : VOID
  BEGIN
  NETWORK
       A   M 0.1;
       =   M 119.3;
  NETWORK
       A   M 0.0;
       =   M 119.6;
  NETWORK
       A   M 0.0;
       =   M 119.7;
  NETWORK
       OPN DB 110;
       L   DBW 38;
       T   MW 206;
       L   DBW 238;
       T   MW 204;
       L   MB 119;
       T   MB 200;
       A   I 33.6;
       =   M 201.1;
       A   I 33.7;
       =   M 201.2;
  NETWORK
       CALL FC 16;
  NETWORK
       OPN DB 110;
       A   M 201.0;
       =   Q 19.7;
       AN  Q 19.7;
       =   Q 19.6;
       L   MB 200;
       T   MB 119;
       L   MW 204;
       T   DBW 238;
       L   MW 206;
       T   DBW 38;
  NETWORK
       OPN DB 118;
       L   MB 202;
       T   DBB 28;
       //;


END_FUNCTION

FUNCTION FC 113 : VOID
  BEGIN
  NETWORK
       A   M 0.1;
       =   M 120.1;
  NETWORK
       A   M 0.1;
       =   M 120.2;
  NETWORK
       O   M 184.2;
       O   M 184.0;
       ON  I 32.2;
       ON  M 175.4;
       =   M 120.3;
  NETWORK
       OPN DB 110;
       O(;
       A   M 175.4;
       AN  M 184.1;
       A   M 103.0;
       );
       O   DBX 40.3;
       =   M 120.6;
  NETWORK
       A   M 0.0;
       =   M 120.7;
  NETWORK
       OPN DB 110;
       L   DBW 40;
       T   MW 206;
       L   DBW 240;
       T   MW 204;
       L   MB 120;
       T   MB 200;
       AN  I 31.7;
       =   M 201.1;
       A   I 32.0;
       =   M 201.2;
  NETWORK
       CALL FC 16;
  NETWORK
       OPN DB 110;
       A   M 201.0;
       =   Q 12.6;
       L   MB 200;
       T   MB 120;
       L   MW 204;
       T   DBW 240;
       L   MW 206;
       T   DBW 40;
  NETWORK
       OPN DB 118;
       L   MB 202;
       T   DBB 26;
       //;


END_FUNCTION

FUNCTION FC 114 : VOID
  BEGIN
  NETWORK
       A   M 0.1;
       =   M 121.3;
  NETWORK
       A   M 0.0;
       =   M 121.6;
  NETWORK
       A   M 0.0;
       =   M 121.7;
  NETWORK
       OPN DB 110;
       L   DBW 42;
       T   MW 206;
       L   DBW 242;
       T   MW 204;
       L   MB 121;
       T   MB 200;
       A   Q 0.2;
       =   M 201.1;
       AN  Q 0.2;
       =   M 201.2;
  NETWORK
       CALL FC 16;
  NETWORK
       A   M 201.0;
       =   Q 0.2;
       L   MB 200;
       T   MB 121;
       L   MW 204;
       T   DBW 242;
       L   MW 206;
       T   DBW 42;
  NETWORK
       OPN DB 118;
       L   MB 202;
       T   DBB 30;


END_FUNCTION

FUNCTION FC 115 : VOID
  BEGIN
  NETWORK
       AN  I 24.5;
       =   M 122.3;
  NETWORK
       A   M 0.0;
       =   M 122.6;
  NETWORK
       A   M 0.0;
       =   M 122.7;
  NETWORK
       OPN DB 110;
       L   DBW 44;
       T   MW 206;
       L   DBW 244;
       T   MW 204;
       L   MB 122;
       T   MB 200;
       A   Q 14.7;
       =   M 201.1;
       AN  Q 14.7;
       =   M 201.2;
  NETWORK
       CALL FC 16;
  NETWORK
       A   M 201.0;
       =   Q 14.7;
       L   MB 200;
       T   MB 122;
       L   MW 204;
       T   DBW 244;
       L   MW 206;
       T   DBW 44;
  NETWORK
       OPN DB 118;
       L   MB 202;
       T   DBB 33;
       //;


END_FUNCTION

FUNCTION FC 116 : VOID
  BEGIN
  NETWORK
       A   M 0.1;
       =   M 123.3;
  NETWORK
       A   M 0.0;
       =   M 123.6;
  NETWORK
       A   M 0.0;
       =   M 123.7;
  NETWORK
       OPN DB 110;
       L   DBW 46;
       T   MW 206;
       L   DBW 246;
       T   MW 204;
       L   MB 123;
       T   MB 200;
       A   I 44.6;
       =   M 201.1;
       AN  I 44.6;
       =   M 201.2;
  NETWORK
       CALL FC 17;
  NETWORK
       A   M 201.0;
       =   Q 11.4;
       L   MB 200;
       T   MB 123;
       L   MW 204;
       T   DBW 246;
       L   MW 206;
       T   DBW 46;
  NETWORK
       OPN DB 118;
       L   MB 202;
       T   DBB 32;
  NETWORK


END_FUNCTION

FUNCTION FC 117 : VOID
    //XEV-162.1
    //
  BEGIN
  NETWORK
       O   I 11.6;
       ON  I 11.7;
       =   M 127.1;
  NETWORK
       ON  I 11.6;
       O   I 11.7;
       =   M 127.2;
  NETWORK
       A   M 0.1;
       =   M 127.3;
  NETWORK
       A   M 0.0;
       =   M 127.6;
  NETWORK
       A   M 0.0;
       =   M 127.7;
  NETWORK
       OPN DB 110;
       L   DBW 48;
       T   MW 206;
       L   DBW 248;
       T   MW 204;
       L   MB 127;
       T   MB 200;
       A   I 11.6;
       =   M 201.1;
       A   I 11.7;
       =   M 201.2;
  NETWORK
       CALL FC 16;
  NETWORK
       OPN DB 110;
       A   M 201.0;
       =   M 201.0;
       L   MB 200;
       T   MB 127;
       L   MW 204;
       T   DBW 248;
       L   MW 206;
       T   DBW 48;
  NETWORK
       OPN DB 118;
       L   MB 202;
       T   DBB 35;


END_FUNCTION

FUNCTION FC 118 : VOID
  BEGIN
  NETWORK
       O   I 33.6;
       ON  I 33.7;
       =   M 128.1;
  NETWORK
       ON  I 33.6;
       O   I 33.7;
       =   M 128.2;
  NETWORK
       A   M 0.1;
       =   M 128.3;
  NETWORK
       A   M 0.0;
       =   M 128.6;
  NETWORK
       A   M 0.0;
       =   M 128.7;
  NETWORK
       OPN DB 110;
       L   DBW 50;
       T   MW 206;
       L   DBW 250;
       T   MW 204;
       L   MB 128;
       T   MB 200;
       A   I 33.6;
       =   M 201.1;
       A   I 33.7;
       =   M 201.2;
  NETWORK
       CALL FC 16;
  NETWORK
       OPN DB 110;
       A   M 201.0;
       =   M 201.0;
       L   MB 200;
       T   MB 128;
       L   MW 204;
       T   DBW 250;
       L   MW 206;
       T   DBW 50;
  NETWORK
       OPN DB 118;
       L   MB 202;
       T   DBB 34;


END_FUNCTION


FUNCTION FC 119 : VOID
  BEGIN
  NETWORK
       O   I 8.5;
       ON  I 7.0;
       =   M 129.1;
  NETWORK
       ON  I 8.5;
       O   I 7.0;
       =   M 129.2;
  NETWORK
       A   M 0.1;
       =   M 129.3;
  NETWORK
       A   M 0.0;
       =   M 129.6;
  NETWORK
       A   M 0.0;
       =   M 129.7;
  NETWORK
       OPN DB 110;
       L   DBW 52;
       T   MW 206;
       L   DBW 252;
       T   MW 204;
       L   MB 129;
       T   MB 200;
       A   I 8.5;
       =   M 201.1;
       A   I 7.0;
       =   M 201.2;
  NETWORK
       CALL FC 16;
  NETWORK
       OPN DB 110;
       A   M 201.0;
       =   M 201.0;
       L   MB 200;
       T   MB 129;
       L   MW 204;
       T   DBW 252;
       L   MW 206;
       T   DBW 52;
  NETWORK
       OPN DB 118;
       L   MB 202;
       T   DBB 37;


END_FUNCTION

FUNCTION FC 120 : VOID
  BEGIN
  NETWORK

       CALL FC 31
        ( ANA    :=  PIW 130
        , OPTI   :=  2#0000000000000000
        , _DB    :=  DB 150
        , VAN    :=  +0.0000000E+00
        , TOT    :=  +0.1000000E+03
        , UITG   :=  DBD 4
        , UITF   :=  DBW 260
        );
       //;
       CALL FC 31
        ( ANA    :=  PIW 132
        , OPTI   :=  2#0000000000000000
        , _DB    :=  DB 150
        , VAN    :=  +0.0000000E+00
        , TOT    :=  +0.1000000E+03
        , UITG   :=  DBD 8
        , UITF   :=  DBW 260
        );
       //;
       CALL FC 31
        ( ANA    :=  PIW 136
        , OPTI   :=  2#0000000000000000
        , _DB    :=  DB 150
        , VAN    :=  +0.0000000E+00
        , TOT    :=  +0.1000000E+03
        , UITG   :=  DBD 16
        , UITF   :=  DBW 260
        );
       //;
       CALL FC 31
        ( ANA    :=  PIW 138
        , OPTI   :=  2#0000000000000000
        , _DB    :=  DB 150
        , VAN    :=  +0.0000000E+00
        , TOT    :=  +0.1000000E+03
        , UITG   :=  DBD 20
        , UITF   :=  DBW 260
        );
       //;
       CALL FC 31
        ( ANA    :=  PIW 140
        , OPTI   :=  2#0000000000000000
        , _DB    :=  DB 150
        , VAN    :=  +0.0000000E+00
        , TOT    :=  +0.0000000E+00
        , UITG   :=  DBD 24
        , UITF   :=  DBW 260
        );
       //;
       CALL FC 31
        ( ANA    :=  PIW 142
        , OPTI   :=  2#0000000000000000
        , _DB    :=  DB 150
        , VAN    :=  +0.2000000E+01
        , TOT    :=  +0.1200000E+02
        , UITG   :=  DBD 28
        , UITF   :=  DBW 260
        );
  NETWORK
       CALL FC 31
        ( ANA    :=  PIW 144
        , OPTI   :=  2#0000000000000000
        , _DB    :=  DB 150
        , VAN    :=  +0.0000000E+00
        , TOT    :=  +0.1200000E+04
        , UITG   :=  DBD 32
        , UITF   :=  DBW 260
        );
       //;
       CALL FC 31
        ( ANA    :=  PIW 146
        , OPTI   :=  2#0000000000000000
        , _DB    :=  DB 150
        , VAN    :=  +0.0000000E+00
        , TOT    :=  +0.9950000E+03
        , UITG   :=  DBD 36
        , UITF   :=  DBW 260
        );
       //;
       CALL FC 31
        ( ANA    :=  PIW 152
        , OPTI   :=  2#0000000000000000
        , _DB    :=  DB 150      // QI-157
        , VAN    :=  -0.6499999E+01
        , TOT    :=  +0.2500000E+02
        , UITG   :=  DBD 48
        , UITF   :=  DBW 260
        );
       //;
       CALL FC 31
        ( ANA    :=  PIW 158
        , OPTI   :=  2#0000000000000000
        , _DB    :=  DB 150
        , VAN    :=  +0.0000000E+00
        , TOT    :=  +0.5600000E+03
        , UITG   :=  DBD 60
        , UITF   :=  DBW 260
        );
  NETWORK
       CALL FC 31
        ( ANA    :=  PIW 160
        , OPTI   :=  2#0000000000000000
        , _DB    :=  DB 150
        , VAN    :=  +0.0000000E+00
        , TOT    :=  +0.5600000E+03
        , UITG   :=  DBD 64
        , UITF   :=  DBW 260
        );
       //;
       CALL FC 31
        ( ANA    :=  PIW 162
        , OPTI   :=  2#0000000000000000
        , _DB    :=  DB 150
        , VAN    :=  +0.0000000E+00
        , TOT    :=  +0.5600000E+03
        , UITG   :=  DBD 68
        , UITF   :=  DBW 260
        );
       //;
       CALL FC 31
        ( ANA    :=  PIW 164
        , OPTI   :=  2#0000000000000000
        , _DB    :=  DB 150
        , VAN    :=  +0.0000000E+00
        , TOT    :=  +0.1000000E+03
        , UITG   :=  DBD 72
        , UITF   :=  DBW 260
        );
       //;
       CALL FC 31
        ( ANA    :=  PIW 166
        , OPTI   :=  2#0000000000000000
        , _DB    :=  DB 150
        , VAN    :=  +0.4890000E+01
        , TOT    :=  +0.2500000E+03
        , UITG   :=  DBD 76
        , UITF   :=  DBW 260
        );
       //;
       CALL FC 31
        ( ANA    :=  PIW 168
        , OPTI   :=  2#0000000000000000
        , _DB    :=  DB 150
        , VAN    :=  +0.4890000E+01
        , TOT    :=  +0.2500000E+03
        , UITG   :=  DBD 80
        , UITF   :=  DBW 260
        );
       //;
       CALL FC 31
        ( ANA    :=  PIW 172
        , OPTI   :=  2#0000000000000000
        , _DB    :=  DB 150
        , VAN    :=  +0.0000000E+00
        , TOT    :=  +0.2600000E+03
        , UITG   :=  DBD 88
        , UITF   :=  DBW 260
        );
       //;
       CALL FC 31
        ( ANA    :=  PIW 174
        , OPTI   :=  2#0000000000000000
        , _DB    :=  DB 150
        , VAN    :=  +0.2000000E+01
        , TOT    :=  +0.1200000E+02
        , UITG   :=  DBD 92
        , UITF   :=  DBW 260
        );
  NETWORK
       CALL FC 31              // PI-920.3
        ( ANA    :=  PIW 176
        , OPTI   :=  2#0000000000000000
        , _DB    :=  DB 150
        , VAN    :=  -0.2500000E+01
        , TOT    :=  +0.1000000E+02
        , UITG   :=  DBD 96
        , UITF   :=  DBW 260
        );
       //;
       CALL FC 31
        ( ANA    :=  PIW 178
        , OPTI   :=  2#0000000000000000
        , _DB    :=  DB 150
        , VAN    :=  +0.0000000E+00
        , TOT    :=  +0.1500000E+03
        , UITG   :=  DBD 100
        , UITF   :=  DBW 260
        );
       //;
       CALL FC 31
        ( ANA    :=  PIW 180
        , OPTI   :=  2#0000000000000000
        , _DB    :=  DB 150
        , VAN    :=  +0.0000000E+00
        , TOT    :=  +0.5000000E+02
        , UITG   :=  DBD 104
        , UITF   :=  DBW 260
        );
       //;
       CALL FC 31
        ( ANA    :=  PIW 182
        , OPTI   :=  2#0000000000000000
        , _DB    :=  DB 150
        , VAN    :=  +0.0000000E+00
        , TOT    :=  +0.5000000E+02
        , UITG   :=  DBD 108
        , UITF   :=  DBW 260
        );
       //;
       CALL FC 31
        ( ANA    :=  PIW 184
        , OPTI   :=  2#0000000000000000
        , _DB    :=  DB 150
        , VAN    :=  +0.0000000E+00
        , TOT    :=  +0.5000000E+02
        , UITG   :=  DBD 112
        , UITF   :=  DBW 260
        );
       //;
       CALL FC 31
        ( ANA    :=  PIW 186
        , OPTI   :=  2#0000000000000000
        , _DB    :=  DB 150
        , VAN    :=  +0.0000000E+00
        , TOT    :=  +0.1500000E+03
        , UITG   :=  DBD 116
        , UITF   :=  DBW 260
        );
       //;
       CALL FC 31
        ( ANA    :=  PIW 188
        , OPTI   :=  2#0000000000000000
        , _DB    :=  DB 150
        , VAN    :=  +0.0000000E+00
        , TOT    :=  +0.1500000E+03
        , UITG   :=  DBD 120
        , UITF   :=  DBW 260
        );
       //;
       CALL FC 31
        ( ANA    :=  PIW 190
        , OPTI   :=  2#0000000000000000
        , _DB    :=  DB 150
        , VAN    :=  -0.9999998E+01
        , TOT    :=  +0.1000000E+02
        , UITG   :=  DBD 124
        , UITF   :=  DBW 260
        );
  NETWORK
       CALL FC 31
        ( ANA    :=  PIW 192
        , OPTI   :=  2#0000000000000000
        , _DB    :=  DB 150
        , VAN    :=  -0.1250000E+02
        , TOT    :=  +0.5000000E+02
        , UITG   :=  DBD 128
        , UITF   :=  DBW 260
        );
       //;
       CALL FC 31              // dPIC-166
        ( ANA    :=  PIW 194
        , OPTI   :=  2#0000000000000000
        , _DB    :=  DB 150
        , VAN    :=  +0.3000000E+00
        , TOT    :=  +0.2000000E+02
        , UITG   :=  DBD 132
        , UITF   :=  DBW 260
        );
       //;
       CALL FC 31
        ( ANA    :=  PIW 196
        , OPTI   :=  2#0000000000000000
        , _DB    :=  DB 150
        , VAN    :=  +0.2000000E+01
        , TOT    :=  +0.1200000E+02
        , UITG   :=  DBD 136
        , UITF   :=  DBW 260
        );
       //;
       CALL FC 31
        ( ANA    :=  PIW 198
        , OPTI   :=  2#0000000000000000
        , _DB    :=  DB 150
        , VAN    :=  +0.2000000E+01
        , TOT    :=  +0.1200000E+02
        , UITG   :=  DBD 140
        , UITF   :=  DBW 260
        );
       //;
       CALL FC 31
        ( ANA    :=  PIW 200
        , OPTI   :=  2#0000000000000000
        , _DB    :=  DB 150
        , VAN    :=  +0.2000000E+01
        , TOT    :=  +0.1200000E+02
        , UITG   :=  DBD 144
        , UITF   :=  DBW 260
        );
  NETWORK
       CALL FC 31
        ( ANA    :=  PIW 208
        , OPTI   :=  2#0000000000000000
        , _DB    :=  DB 150
        , VAN    :=  +0.0000000E+00
        , TOT    :=  +0.1000000E+03
        , UITG   :=  DBD 160
        , UITF   :=  DBW 260
        );
       //;
       CALL FC 31
        ( ANA    :=  PIW 210
        , OPTI   :=  2#0000000000000000
        , _DB    :=  DB 150
        , VAN    :=  +0.0000000E+00
        , TOT    :=  +0.1000000E+03
        , UITG   :=  DBD 164
        , UITF   :=  DBW 260
        );
       //;
       CALL FC 31
        ( ANA    :=  PIW 214
        , OPTI   :=  2#0000000000000000
        , _DB    :=  DB 150
        , VAN    :=  -0.6499999E+01
        , TOT    :=  +0.1000000E+03
        , UITG   :=  DBD 172
        , UITF   :=  DBW 260
        );
       //;
       CALL FC 31
        ( ANA    :=  PIW 218
        , OPTI   :=  2#0000000000000000
        , _DB    :=  DB 150
        , VAN    :=  +0.0000000E+00
        , TOT    :=  +0.1000000E+03
        , UITG   :=  DBD 180
        , UITF   :=  DBW 260
        );
       //;
       CALL FC 31
        ( ANA    :=  PIW 220
        , OPTI   :=  2#0000000000000000
        , _DB    :=  DB 150
        , VAN    :=  +0.0000000E+00
        , TOT    :=  +0.1000000E+03
        , UITG   :=  DBD 184
        , UITF   :=  DBW 260
        );
  NETWORK
       CALL FC 31
        ( ANA    :=  PIW 224
        , OPTI   :=  2#0000000000000000
        , _DB    :=  DB 150
        , VAN    :=  +0.2000000E+01
        , TOT    :=  +0.1200000E+02
        , UITG   :=  DBD 192
        , UITF   :=  DBW 260
        );
       //;
       CALL FC 31
        ( ANA    :=  PIW 226
        , OPTI   :=  2#0000000000000000
        , _DB    :=  DB 150
        , VAN    :=  +0.2000000E+01
        , TOT    :=  +0.1200000E+02
        , UITG   :=  DBD 196
        , UITF   :=  DBW 260
        );
       //;
       CALL FC 31
        ( ANA    :=  PIW 228
        , OPTI   :=  2#0000000000000000
        , _DB    :=  DB 150
        , VAN    :=  +0.2000000E+01
        , TOT    :=  +0.1200000E+02
        , UITG   :=  DBD 200
        , UITF   :=  DBW 260
        );
       //;
       CALL FC 31
        ( ANA    :=  PIW 230
        , OPTI   :=  2#0000000000000000
        , _DB    :=  DB 150
        , VAN    :=  +0.1125000E+04
        , TOT    :=  +0.1380000E+04
        , UITG   :=  DBD 204
        , UITF   :=  DBW 260
        );
  NETWORK
       CALL FC 31
        ( ANA    :=  PIW 240
        , OPTI   :=  2#0000000000000000
        , _DB    :=  DB 150
        , VAN    :=  +0.0000000E+00
        , TOT    :=  +0.1000000E+03
        , UITG   :=  DBD 224
        , UITF   :=  DBW 260
        );
       //;
       CALL FC 31
        ( ANA    :=  PIW 242
        , OPTI   :=  2#0000000000000000
        , _DB    :=  DB 150
        , VAN    :=  +0.0000000E+00
        , TOT    :=  +0.1000000E+03
        , UITG   :=  DBD 228
        , UITF   :=  DBW 260
        );
       //;
       CALL FC 31
        ( ANA    :=  PIW 246
        , OPTI   :=  2#0000000000000000
        , _DB    :=  DB 150
        , VAN    :=  +0.0000000E+00
        , TOT    :=  +0.1000000E+03
        , UITG   :=  DBD 232
        , UITF   :=  DBW 260
        );
       //;
       CALL FC 31
        ( ANA    :=  PIW 244
        , OPTI   :=  2#0000000000000000
        , _DB    :=  DB 150
        , VAN    :=  +0.0000000E+00
        , TOT    :=  +0.1000000E+03
        , UITG   :=  DBD 236
        , UITF   :=  DBW 260
        );
       //;
       CALL FC 31
        ( ANA    :=  PIW 248
        , OPTI   :=  2#0000000000000000
        , _DB    :=  DB 150
        , VAN    :=  -0.9999998E+02
        , TOT    :=  +0.1000000E+03
        , UITG   :=  DBD 240
        , UITF   :=  DBW 260
        );
       //;
       CALL FC 31
        ( ANA    :=  PIW 250
        , OPTI   :=  2#0000000000000000
        , _DB    :=  DB 150
        , VAN    :=  +0.0000000E+00
        , TOT    :=  +0.1000000E+04
        , UITG   :=  DBD 244
        , UITF   :=  DBW 260
        );
       //;
       CALL FC 31
        ( ANA    :=  PIW 252
        , OPTI   :=  2#0000000000000000
        , _DB    :=  DB 150
        , VAN    :=  +0.2000000E+01
        , TOT    :=  +0.1200000E+02
        , UITG   :=  DBD 248
        , UITF   :=  DBW 260
        );
       //;
       CALL FC 31
        ( ANA    :=  PIW 254
        , OPTI   :=  2#0000000000000000
        , _DB    :=  DB 150
        , VAN    :=  +0.2000000E+01
        , TOT    :=  +0.1200000E+02
        , UITG   :=  DBD 252
        , UITF   :=  DBW 260
        );


END_FUNCTION

FUNCTION FC 121 : VOID
  BEGIN
  NETWORK
       CALL FC 31
        ( ANA    :=  PIW 0
        , OPTI   :=  2#0000000000000001
        , _DB    :=  DB 151
        , VAN    :=  +0.0000000E+00
        , TOT    :=  +0.3000000E+04
        , UITG   :=  DBD 0
        , UITF   :=  DBW 260
        );
       //;
       CALL FC 31
        ( ANA    :=  PIW 4
        , OPTI   :=  2#0000000000000000
        , _DB    :=  DB 151
        , VAN    :=  +0.6000000E+02
        , TOT    :=  +0.1000000E+03
        , UITG   :=  DBD 8
        , UITF   :=  DBW 260
        );
       //;
       CALL FC 31
        ( ANA    :=  PIW 6
        , OPTI   :=  2#0000000000000001
        , _DB    :=  DB 151      // PT-918
        , VAN    :=  +0.0000000E+00
        , TOT    :=  +0.9000000E+01
        , UITG   :=  DBD 12
        , UITF   :=  DBW 260
        );
       //;
       CALL FC 31
        ( ANA    :=  PIW 8
        , OPTI   :=  2#0000000000000001
        , _DB    :=  DB 151
        , VAN    :=  +0.0000000E+00
        , TOT    :=  +0.1000000E+03
        , UITG   :=  DBD 16
        , UITF   :=  DBW 260
        );
       //;
       CALL FC 31
        ( ANA    :=  PIW 10
        , OPTI   :=  2#0000000000000000
        , _DB    :=  DB 151
        , VAN    :=  +0.0000000E+00
        , TOT    :=  +0.1200000E+04
        , UITG   :=  DBD 16
        , UITF   :=  DBW 260
        );
       //;
       CALL FC 31
        ( ANA    :=  PIW 12
        , OPTI   :=  2#0000000000000000
        , _DB    :=  DB 151
        , VAN    :=  +0.0000000E+00
        , TOT    :=  +0.1200000E+04
        , UITG   :=  DBD 24
        , UITF   :=  DBW 260
        );
       //;
       CALL FC 31
        ( ANA    :=  PIW 14
        , OPTI   :=  2#0000000000000000
        , _DB    :=  DB 151
        , VAN    :=  -0.2500000E+01
        , TOT    :=  +0.7500000E+01
        , UITG   :=  DBD 28
        , UITF   :=  DBW 260
        );
       //;
       CALL FC 31
        ( ANA    :=  PIW 18
        , OPTI   :=  2#0000000000000001
        , _DB    :=  DB 151
        , VAN    :=  +0.0000000E+00
        , TOT    :=  +0.1000000E+03
        , UITG   :=  DBD 36
        , UITF   :=  DBW 260
        );
       //;
       AN  M 190.1;
       JCN   X000;
     CALL FC 31
        ( ANA    :=  PIW 22
        , OPTI   :=  2#0000000000000001
        , _DB    :=  DB 151
        , VAN    :=  +0.0000000E+00
        , TOT    :=  +0.6000000E+02
        , UITG   :=  DBD 44
        , UITF   :=  DBW 260
        );
  X000: NOP 0;
       //;
       A   M 190.1;
       JCN   X001;
     CALL FC 31
        ( ANA    :=  PIW 134
        , OPTI   :=  2#0000000000000000
        , _DB    :=  DB 151
        , VAN    :=  +0.0000000E+00
        , TOT    :=  +0.6000000E+02
        , UITG   :=  DBD 44
        , UITF   :=  DBW 260
        );
  X001: NOP 0;
  NETWORK
       CALL FC 31
        ( ANA    :=  PIW 40
        , OPTI   :=  2#0000000000000001
        , _DB    :=  DB 151
        , VAN    :=  +0.0000000E+00
        , TOT    :=  +0.6200000E+04
        , UITG   :=  DBD 80
        , UITF   :=  DBW 260
        );
       //;
       CALL FC 31
        ( ANA    :=  PIW 42
        , OPTI   :=  2#0000000000000001
        , _DB    :=  DB 151
        , VAN    :=  +0.0000000E+00
        , TOT    :=  +0.6200000E+04
        , UITG   :=  DBD 84
        , UITF   :=  DBW 260
        );
       //;
       CALL FC 31
        ( ANA    :=  PIW 48
        , OPTI   :=  2#0000000000000000
        , _DB    :=  DB 151
        , VAN    :=  -0.2659999E+03
        , TOT    :=  +0.2660000E+03
        , UITG   :=  DBD 96
        , UITF   :=  DBW 260
        );
       //;
       CALL FC 31
        ( ANA    :=  PIW 52
        , OPTI   :=  2#0000000000000000
        , _DB    :=  DB 151
        , VAN    :=  -0.2659999E+03
        , TOT    :=  +0.2660000E+03
        , UITG   :=  DBD 104
        , UITF   :=  DBW 260
        );
       //;
       CALL FC 31
        ( ANA    :=  PIW 54
        , OPTI   :=  2#0000000000000000
        , _DB    :=  DB 151
        , VAN    :=  -0.2659999E+03
        , TOT    :=  +0.2660000E+03
        , UITG   :=  DBD 108
        , UITF   :=  DBW 260
        );
       //;
       CALL FC 31
        ( ANA    :=  PIW 64
        , OPTI   :=  2#0000000000000001
        , _DB    :=  DB 151
        , VAN    :=  +0.0000000E+00
        , TOT    :=  +0.2500000E+03
        , UITG   :=  DBD 128
        , UITF   :=  DBW 260
        );
       //;
       CALL FC 31
        ( ANA    :=  PIW 66
        , OPTI   :=  2#0000000000000001
        , _DB    :=  DB 151
        , VAN    :=  +0.0000000E+00
        , TOT    :=  +0.2500000E+03
        , UITG   :=  DBD 132
        , UITF   :=  DBW 260
        );
       //;
       CALL FC 31
        ( ANA    :=  PIW 80
        , OPTI   :=  2#0000000000000001
        , _DB    :=  DB 151
        , VAN    :=  +0.1000000E+03
        , TOT    :=  +0.0000000E+00
        , UITG   :=  DBD 160
        , UITF   :=  DBW 260
        );
       //;
       CALL FC 31
        ( ANA    :=  PIW 82
        , OPTI   :=  2#0000000000000001
        , _DB    :=  DB 151
        , VAN    :=  +0.0000000E+00
        , TOT    :=  +0.1200000E+04
        , UITG   :=  DBD 164
        , UITF   :=  DBW 260
        );
       //;
       CALL FC 31
        ( ANA    :=  PIW 84
        , OPTI   :=  2#0000000000000001
        , _DB    :=  DB 151
        , VAN    :=  +0.0000000E+00
        , TOT    :=  +0.2500000E+02
        , UITG   :=  DBD 168
        , UITF   :=  DBW 260
        );
       //;
       CALL FC 31
        ( ANA    :=  PIW 86
        , OPTI   :=  2#0000000000000001
        , _DB    :=  DB 151
        , VAN    :=  +0.0000000E+00
        , TOT    :=  +0.4000000E+03
        , UITG   :=  DBD 172
        , UITF   :=  DBW 260
        );
       CALL FC 31
        ( ANA    :=  PIW 102
        , OPTI   :=  2#0000000000000001
        , _DB    :=  DB 151
        , VAN    :=  +0.0000000E+00
        , TOT    :=  +0.1000000E+03
        , UITG   :=  DBD 204
        , UITF   :=  DBW 260
        );
       //;
       CALL FC 31
        ( ANA    :=  PIW 90
        , OPTI   :=  2#0000000000000001
        , _DB    :=  DB 151
        , VAN    :=  +0.0000000E+00
        , TOT    :=  +0.1000000E+03
        , UITG   :=  DBD 180
        , UITF   :=  DBW 260
        );
       //;
       CALL FC 31
        ( ANA    :=  PIW 104
        , OPTI   :=  2#0000000000000001
        , _DB    :=  DB 151
        , VAN    :=  +0.0000000E+00
        , TOT    :=  +0.1000000E+03
        , UITG   :=  DBD 184
        , UITF   :=  DBW 260
        );
       //;
       CALL FC 31
        ( ANA    :=  PIW 94
        , OPTI   :=  2#0000000000000001
        , _DB    :=  DB 151
        , VAN    :=  +0.0000000E+00
        , TOT    :=  +0.2000000E+02
        , UITG   :=  DBD 188
        , UITF   :=  DBW 260
        );
  NETWORK
       CALL FC 31
        ( ANA    :=  PIW 96
        , OPTI   :=  2#0000000000000001
        , _DB    :=  DB 151
        , VAN    :=  +0.0000000E+00
        , TOT    :=  +0.3000000E+03
        , UITG   :=  DBD 192
        , UITF   :=  DBW 260
        );
       //;
       CALL FC 31
        ( ANA    :=  PIW 104
        , OPTI   :=  2#0000000000000001
        , _DB    :=  DB 151
        , VAN    :=  +0.0000000E+00
        , TOT    :=  +0.1000000E+03
        , UITG   :=  DBD 184
        , UITF   :=  DBW 260
        );
       //;
       CALL FC 31
        ( ANA    :=  PIW 106
        , OPTI   :=  2#0000000000000001
        , _DB    :=  DB 151      // PT-920.1
        , VAN    :=  +0.0000000E+00
        , TOT    :=  +0.1600000E+02
        , UITG   :=  DBD 212
        , UITF   :=  DBW 260
        );
       //;
       CALL FC 31
        ( ANA    :=  PIW 108
        , OPTI   :=  2#0000000000000001
        , _DB    :=  DB 151
        , VAN    :=  +0.0000000E+00
        , TOT    :=  +0.1000000E+02
        , UITG   :=  DBD 216
        , UITF   :=  DBW 260     // PT-920.2
        );
       //;
       AN  M 190.3;
       JCN   X002;
     CALL FC 31
        ( ANA    :=  PIW 110
        , OPTI   :=  2#0000000000000001
        , _DB    :=  DB 151
        , VAN    :=  +0.0000000E+00
        , TOT    :=  +0.3500000E+02
        , UITG   :=  DBD 220
        , UITF   :=  DBW 260
        );
  X002: NOP 0;
       //;
       A   M 190.3;
       JCN   X003;
     CALL FC 31
        ( ANA    :=  PIW 20
        , OPTI   :=  2#0000000000000001
        , _DB    :=  DB 151
        , VAN    :=  +0.0000000E+00
        , TOT    :=  +0.3500000E+02
        , UITG   :=  DBD 220
        , UITF   :=  DBW 260
        );
  X003: NOP 0;
       //;
       //;
       CALL FC 31
        ( ANA    :=  PIW 118
        , OPTI   :=  2#0000000000000010
        , _DB    :=  DB 151
        , VAN    :=  +0.0000000E+00
        , TOT    :=  +0.0000000E+00
        , UITG   :=  DBD 236
        , UITF   :=  DBW 260
        );
       //;


END_FUNCTION

FUNCTION FC 122 : VOID
  BEGIN
  NETWORK
       CALL FC 31
        ( ANA    :=  PIW 128
        , OPTI   :=  2#0000000000000010
        , _DB    :=  DB 152
        , VAN    :=  +0.0000000E+00
        , TOT    :=  +0.1235000E+04
        , UITG   :=  DBD 0
        , UITF   :=  DBW 260
        );
       //;
       CALL FC 31
        ( ANA    :=  PIW 130     // TI-151
        , OPTI   :=  2#0000000000000010
        , _DB    :=  DB 152
        , VAN    :=  +0.0000000E+00
        , TOT    :=  +0.1235000E+04
        , UITG   :=  DBD 4
        , UITF   :=  DBW 260
        );
       //;
       CALL FC 31
        ( ANA    :=  PIW 132
        , OPTI   :=  2#0000000000000010
        , _DB    :=  DB 152
        , VAN    :=  +0.0000000E+00
        , TOT    :=  +0.1235000E+04
        , UITG   :=  DBD 8
        , UITF   :=  DBW 260
        );
       //;
       CALL FC 31
        ( ANA    :=  PIW 134
        , OPTI   :=  2#0000000000000010
        , _DB    :=  DB 152
        , VAN    :=  +0.0000000E+00
        , TOT    :=  +0.1235000E+04
        , UITG   :=  DBD 12
        , UITF   :=  DBW 260
        );
       //;
       CALL FC 31
        ( ANA    :=  PIW 136
        , OPTI   :=  2#0000000000000010
        , _DB    :=  DB 152
        , VAN    :=  +0.0000000E+00
        , TOT    :=  +0.1235000E+04
        , UITG   :=  DBD 16
        , UITF   :=  DBW 260
        );
       //;
       CALL FC 31
        ( ANA    :=  PIW 138
        , OPTI   :=  2#0000000000000010
        , _DB    :=  DB 152
        , VAN    :=  +0.0000000E+00
        , TOT    :=  +0.1235000E+04
        , UITG   :=  DBD 20
        , UITF   :=  DBW 260
        );
       //;
       CALL FC 31              // TI-158.2
        ( ANA    :=  PIW 140
        , OPTI   :=  2#0000000000000010
        , _DB    :=  DB 152
        , VAN    :=  +0.0000000E+00
        , TOT    :=  +0.1200000E+04
        , UITG   :=  DBD 24
        , UITF   :=  DBW 260
        );
       //;
       CALL FC 31
        ( ANA    :=  PIW 142     // TI-149.4
        , OPTI   :=  2#0000000000000010
        , _DB    :=  DB 152
        , VAN    :=  +0.0000000E+00
        , TOT    :=  +0.1235000E+04
        , UITG   :=  DBD 28
        , UITF   :=  DBW 260
        );
  NETWORK
       CALL FC 31
        ( ANA    :=  PIW 144
        , OPTI   :=  2#0000000000000010
        , _DB    :=  DB 152
        , VAN    :=  +0.0000000E+00
        , TOT    :=  +0.1235000E+04
        , UITG   :=  DBD 32
        , UITF   :=  DBW 260
        );
       //;
       CALL FC 31
        ( ANA    :=  PIW 146
        , OPTI   :=  2#0000000000000010
        , _DB    :=  DB 152
        , VAN    :=  +0.0000000E+00
        , TOT    :=  +0.1235000E+04
        , UITG   :=  DBD 36
        , UITF   :=  DBW 260
        );
       //;
       CALL FC 31
        ( ANA    :=  PIW 148
        , OPTI   :=  2#0000000000000010
        , _DB    :=  DB 152      // TI-161.2
        , VAN    :=  +0.0000000E+00
        , TOT    :=  +0.1235000E+04
        , UITG   :=  DBD 40
        , UITF   :=  DBW 260
        );
       //;
       CALL FC 31
        ( ANA    :=  PIW 150
        , OPTI   :=  2#0000000000000010
        , _DB    :=  DB 152
        , VAN    :=  +0.0000000E+00
        , TOT    :=  +0.1235000E+04
        , UITG   :=  DBD 44
        , UITF   :=  DBW 260
        );
       //;
       CALL FC 31
        ( ANA    :=  PIW 152
        , OPTI   :=  2#0000000000000010
        , _DB    :=  DB 152
        , VAN    :=  +0.0000000E+00
        , TOT    :=  +0.1235000E+04
        , UITG   :=  DBD 48
        , UITF   :=  DBW 260
        );
       //;
       CALL FC 31
        ( ANA    :=  PIW 154
        , OPTI   :=  2#0000000000000010
        , _DB    :=  DB 152
        , VAN    :=  +0.0000000E+00
        , TOT    :=  +0.1235000E+04
        , UITG   :=  DBD 52
        , UITF   :=  DBW 260
        );
       //;
       CALL FC 31
        ( ANA    :=  PIW 156
        , OPTI   :=  2#0000000000000010
        , _DB    :=  DB 152
        , VAN    :=  +0.0000000E+00
        , TOT    :=  +0.1235000E+04
        , UITG   :=  DBD 56
        , UITF   :=  DBW 260
        );
       //;
       CALL FC 31
        ( ANA    :=  PIW 158
        , OPTI   :=  2#0000000000000010
        , _DB    :=  DB 152
        , VAN    :=  +0.0000000E+00
        , TOT    :=  +0.1235000E+04
        , UITG   :=  DBD 60
        , UITF   :=  DBW 260
        );
  NETWORK
       CALL FC 31
        ( ANA    :=  PIW 160
        , OPTI   :=  2#0000000000000010
        , _DB    :=  DB 152
        , VAN    :=  +0.0000000E+00
        , TOT    :=  +0.1235000E+04
        , UITG   :=  DBD 64
        , UITF   :=  DBW 260
        );
       //;
       CALL FC 31
        ( ANA    :=  PIW 162
        , OPTI   :=  2#0000000000000010
        , _DB    :=  DB 152
        , VAN    :=  +0.0000000E+00
        , TOT    :=  +0.1235000E+04
        , UITG   :=  DBD 68
        , UITF   :=  DBW 260
        );
       //;
       CALL FC 31
        ( ANA    :=  PIW 164
        , OPTI   :=  2#0000000000000010
        , _DB    :=  DB 152
        , VAN    :=  +0.0000000E+00
        , TOT    :=  +0.1235000E+04
        , UITG   :=  DBD 72
        , UITF   :=  DBW 260
        );
       //;
       CALL FC 31
        ( ANA    :=  PIW 166
        , OPTI   :=  2#0000000000000010
        , _DB    :=  DB 152
        , VAN    :=  +0.0000000E+00
        , TOT    :=  +0.1235000E+04
        , UITG   :=  DBD 76
        , UITF   :=  DBW 260
        );
       //;
       CALL FC 31
        ( ANA    :=  PIW 170
        , OPTI   :=  2#0000000000000010
        , _DB    :=  DB 152
        , VAN    :=  +0.0000000E+00
        , TOT    :=  +0.1235000E+04
        , UITG   :=  DBD 84
        , UITF   :=  DBW 260
        );
       //;
       CALL FC 31
        ( ANA    :=  PIW 172
        , OPTI   :=  2#0000000000000010
        , _DB    :=  DB 152
        , VAN    :=  +0.0000000E+00
        , TOT    :=  +0.1235000E+04
        , UITG   :=  DBD 88
        , UITF   :=  DBW 260
        );
       //;
       CALL FC 31
        ( ANA    :=  PIW 174
        , OPTI   :=  2#0000000000000010
        , _DB    :=  DB 152
        , VAN    :=  +0.0000000E+00
        , TOT    :=  +0.1235000E+04
        , UITG   :=  DBD 92
        , UITF   :=  DBW 260
        );
  NETWORK
       CALL FC 31
        ( ANA    :=  PIW 176
        , OPTI   :=  2#0000000000000010
        , _DB    :=  DB 152
        , VAN    :=  +0.0000000E+00
        , TOT    :=  +0.1235000E+04
        , UITG   :=  DBD 96
        , UITF   :=  DBW 260
        );
       //;
       CALL FC 31
        ( ANA    :=  PIW 178
        , OPTI   :=  2#0000000000000010
        , _DB    :=  DB 152
        , VAN    :=  +0.0000000E+00
        , TOT    :=  +0.1235000E+04
        , UITG   :=  DBD 100
        , UITF   :=  DBW 260
        );
       //;
       CALL FC 31
        ( ANA    :=  PIW 182
        , OPTI   :=  2#0000000000000010
        , _DB    :=  DB 152
        , VAN    :=  +0.0000000E+00
        , TOT    :=  +0.1235000E+04
        , UITG   :=  DBD 108
        , UITF   :=  DBW 260
        );
       //;
       CALL FC 31
        ( ANA    :=  PIW 184
        , OPTI   :=  2#0000000000000010
        , _DB    :=  DB 152
        , VAN    :=  +0.0000000E+00
        , TOT    :=  +0.1235000E+04
        , UITG   :=  DBD 112
        , UITF   :=  DBW 260
        );
       //;
       CALL FC 31
        ( ANA    :=  PIW 186
        , OPTI   :=  2#0000000000000010
        , _DB    :=  DB 152
        , VAN    :=  +0.0000000E+00
        , TOT    :=  +0.1235000E+04
        , UITG   :=  DBD 116
        , UITF   :=  DBW 260
        );
       //;
       CALL FC 31
        ( ANA    :=  PIW 188
        , OPTI   :=  2#0000000000000010
        , _DB    :=  DB 152
        , VAN    :=  +0.0000000E+00
        , TOT    :=  +0.1235000E+04
        , UITG   :=  DBD 120
        , UITF   :=  DBW 260
        );
       //;
       CALL FC 31
        ( ANA    :=  PIW 190
        , OPTI   :=  2#0000000000000010
        , _DB    :=  DB 152
        , VAN    :=  +0.0000000E+00
        , TOT    :=  +0.1235000E+04
        , UITG   :=  DBD 124
        , UITF   :=  DBW 260
        );
  NETWORK
       CALL FC 31
        ( ANA    :=  PIW 192
        , OPTI   :=  2#0000000000000010
        , _DB    :=  DB 152
        , VAN    :=  +0.0000000E+00
        , TOT    :=  +0.1235000E+04
        , UITG   :=  DBD 128
        , UITF   :=  DBW 260
        );
       //;
       CALL FC 31
        ( ANA    :=  PIW 194
        , OPTI   :=  2#0000000000000010
        , _DB    :=  DB 152
        , VAN    :=  +0.0000000E+00
        , TOT    :=  +0.1235000E+04
        , UITG   :=  DBD 132
        , UITF   :=  DBW 260
        );
       //;
       CALL FC 31
        ( ANA    :=  PIW 196
        , OPTI   :=  2#0000000000000010
        , _DB    :=  DB 152
        , VAN    :=  +0.0000000E+00
        , TOT    :=  +0.1235000E+04
        , UITG   :=  DBD 136
        , UITF   :=  DBW 260
        );
       //;
       CALL FC 31
        ( ANA    :=  PIW 198
        , OPTI   :=  2#0000000000000010
        , _DB    :=  DB 152
        , VAN    :=  +0.0000000E+00
        , TOT    :=  +0.1235000E+04
        , UITG   :=  DBD 140
        , UITF   :=  DBW 260
        );
       //;
       CALL FC 31
        ( ANA    :=  PIW 208
        , OPTI   :=  2#0000000000000010
        , _DB    :=  DB 152
        , VAN    :=  +0.0000000E+00
        , TOT    :=  +0.1235000E+04
        , UITG   :=  DBD 144
        , UITF   :=  DBW 260
        );
       //;
       CALL FC 31
        ( ANA    :=  PIW 210
        , OPTI   :=  2#0000000000000010
        , _DB    :=  DB 152
        , VAN    :=  +0.0000000E+00
        , TOT    :=  +0.1235000E+04
        , UITG   :=  DBD 148
        , UITF   :=  DBW 260
        );
       //;
       CALL FC 31
        ( ANA    :=  PIW 212
        , OPTI   :=  2#0000000000000010
        , _DB    :=  DB 152
        , VAN    :=  +0.0000000E+00
        , TOT    :=  +0.1235000E+04
        , UITG   :=  DBD 152
        , UITF   :=  DBW 260
        );
       //;
       CALL FC 31
        ( ANA    :=  PIW 214
        , OPTI   :=  2#0000000000000010
        , _DB    :=  DB 152
        , VAN    :=  +0.0000000E+00
        , TOT    :=  +0.1235000E+04
        , UITG   :=  DBD 156
        , UITF   :=  DBW 260
        );
       //;


END_FUNCTION

FUNCTION FC 123 : VOID
  BEGIN
  NETWORK
       CALL FC 35
        ( IN     :=  DBD 138
        , VAN    :=  +0.1000000E+03
        , TOT    :=  +0.0000000E+00
        , DBIN   :=  DB 180
        , UIT    :=  PQW 128
        );
       //;
       CALL FC 35
        ( IN     :=  DBD 162
        , VAN    :=  +0.0000000E+00
        , TOT    :=  +0.1000000E+03
        , DBIN   :=  DB 180
        , UIT    :=  PQW 130
        );
       //;
       CALL FC 35
        ( IN     :=  DBD 186
        , VAN    :=  +0.0000000E+00
        , TOT    :=  +0.1000000E+03
        , DBIN   :=  DB 180
        , UIT    :=  PQW 132
        );
       //;
       CALL FC 35
        ( IN     :=  DBD 234
        , VAN    :=  +0.1000000E+03
        , TOT    :=  +0.0000000E+00
        , DBIN   :=  DB 180
        , UIT    :=  PQW 134
        );
       //;
       CALL FC 35
        ( IN     :=  DBD 258
        , VAN    :=  +0.1000000E+03
        , TOT    :=  +0.0000000E+00
        , DBIN   :=  DB 180
        , UIT    :=  PQW 144
        );
       //;
       CALL FC 35
        ( IN     :=  DBD 66
        , VAN    :=  +0.0000000E+00
        , TOT    :=  +0.1000000E+03
        , DBIN   :=  DB 180
        , UIT    :=  PQW 138
        );
       //;
       CALL FC 35
        ( IN     :=  DBD 202
        , VAN    :=  +0.0000000E+00
        , TOT    :=  +0.1000000E+03
        , DBIN   :=  DB 181
        , UIT    :=  PQW 140
        );
       //;
       CALL FC 35
        ( IN     :=  DBD 242
        , VAN    :=  +0.0000000E+00
        , TOT    :=  +0.1000000E+03
        , DBIN   :=  DB 181
        , UIT    :=  PQW 142
        );
  NETWORK
       CALL FC 35
        ( IN     :=  DBD 90
        , VAN    :=  +0.0000000E+00
        , TOT    :=  +0.1000000E+03
        , DBIN   :=  DB 180
        , UIT    :=  PQW 146
        );
       //;
       CALL FC 35
        ( IN     :=  DBD 90
        , VAN    :=  +0.0000000E+00
        , TOT    :=  +0.1000000E+03
        , DBIN   :=  DB 180
        , UIT    :=  PQW 148
        );
       //;
       CALL FC 35
        ( IN     :=  DBD 90
        , VAN    :=  +0.0000000E+00
        , TOT    :=  +0.2000000E+03
        , DBIN   :=  DB 181
        , UIT    :=  PQW 150
        );
       //;
       CALL FC 35
        ( IN     :=  DBD 42
        , VAN    :=  +0.0000000E+00
        , TOT    :=  +0.1000000E+03
        , DBIN   :=  DB 180
        , UIT    :=  PQW 152
        );
       //;
       CALL FC 35
        ( IN     :=  DBD 210
        , VAN    :=  +0.0000000E+00
        , TOT    :=  +0.1000000E+03
        , DBIN   :=  DB 180
        , UIT    :=  PQW 154
        );
       //;
       CALL FC 35
        ( IN     :=  DBD 498
        , VAN    :=  +0.0000000E+00
        , TOT    :=  +0.1000000E+03
        , DBIN   :=  DB 180
        , UIT    :=  PQW 156
        );
       //;
       CALL FC 35
        ( IN     :=  DBD 18
        , VAN    :=  +0.0000000E+00
        , TOT    :=  +0.1000000E+03
        , DBIN   :=  DB 181
        , UIT    :=  PQW 158
        );
  NETWORK
       CALL FC 35
        ( IN     :=  DBD 42
        , VAN    :=  +0.0000000E+00
        , TOT    :=  +0.1000000E+03
        , DBIN   :=  DB 181
        , UIT    :=  PQW 160
        );
       //;
       CALL FC 35
        ( IN     :=  DBD 474
        , VAN    :=  +0.1000000E+03
        , TOT    :=  +0.0000000E+00
        , DBIN   :=  DB 180
        , UIT    :=  PQW 162
        );
       //;
       CALL FC 35
        ( IN     :=  DBD 282
        , VAN    :=  +0.0000000E+00
        , TOT    :=  +0.1000000E+03
        , DBIN   :=  DB 180
        , UIT    :=  PQW 198
        );
       //;
       CALL FC 35
        ( IN     :=  DBD 306
        , VAN    :=  +0.0000000E+00
        , TOT    :=  +0.1000000E+03
        , DBIN   :=  DB 180
        , UIT    :=  PQW 166
        );
       //;
       CALL FC 35
        ( IN     :=  DBD 450
        , VAN    :=  +0.1000000E+03
        , TOT    :=  +0.0000000E+00
        , DBIN   :=  DB 180
        , UIT    :=  PQW 168
        );
       //;
       CALL FC 35
        ( IN     :=  DBD 330
        , VAN    :=  +0.0000000E+00
        , TOT    :=  +0.1000000E+03
        , DBIN   :=  DB 180
        , UIT    :=  PQW 172
        );
       //;
       CALL FC 35
        ( IN     :=  DBD 206
        , VAN    :=  +0.0000000E+00
        , TOT    :=  +0.4000000E+03
        , DBIN   :=  DB 181
        , UIT    :=  PQW 174
        );
  NETWORK
       CALL FC 35
        ( IN     :=  DBD 354
        , VAN    :=  +0.0000000E+00
        , TOT    :=  +0.1000000E+03
        , DBIN   :=  DB 180
        , UIT    :=  PQW 176
        );
       //;
       CALL FC 35
        ( IN     :=  DBD 378
        , VAN    :=  +0.0000000E+00
        , TOT    :=  +0.1000000E+03
        , DBIN   :=  DB 180
        , UIT    :=  PQW 178
        );
       //;
       CALL FC 35
        ( IN     :=  DBD 402
        , VAN    :=  +0.0000000E+00
        , TOT    :=  +0.1000000E+03
        , DBIN   :=  DB 180
        , UIT    :=  PQW 184
        );
       //;
       CALL FC 35
        ( IN     :=  DBD 426
        , VAN    :=  +0.0000000E+00
        , TOT    :=  +0.1000000E+03
        , DBIN   :=  DB 180
        , UIT    :=  PQW 186
        );
       //;
       CALL FC 35
        ( IN     :=  DBD 300
        , VAN    :=  +0.0000000E+00
        , TOT    :=  +0.1000000E+03
        , DBIN   :=  DB 150
        , UIT    :=  PQW 188
        );
       //;
       CALL FC 35
        ( IN     :=  DBD 138
        , VAN    :=  +0.0000000E+00
        , TOT    :=  +0.1000000E+03
        , DBIN   :=  DB 181
        , UIT    :=  PQW 194
        );
       //;
       CALL FC 35
        ( IN     :=  DBD 238
        , VAN    :=  -0.2500000E+02
        , TOT    :=  +0.1000000E+03
        , DBIN   :=  DB 181
        , UIT    :=  PQW 192
        );
       //;
       CALL FC 35
        ( IN     :=  DBD 162
        , VAN    :=  +0.0000000E+00
        , TOT    :=  +0.1000000E+03
        , DBIN   :=  DB 181
        , UIT    :=  PQW 196
        );
       //;
       CALL FC 35
        ( IN     :=  DBD 250
        , VAN    :=  -0.1250000E+02
        , TOT    :=  +0.5000000E+02
        , DBIN   :=  DB 181
        , UIT    :=  PQW 200
        );
       //;


END_FUNCTION

FUNCTION FC 124 : VOID
  BEGIN
  NETWORK
       CALL FC 35
        ( IN     :=  DBD 138
        , VAN    :=  +0.1000000E+03
        , TOT    :=  +0.0000000E+00
        , DBIN   :=  DB 180
        , UIT    :=  PQW 128
        );
       //;
       CALL FC 35
        ( IN     :=  DBD 162
        , VAN    :=  +0.0000000E+00
        , TOT    :=  +0.1000000E+03
        , DBIN   :=  DB 180
        , UIT    :=  PQW 130
        );
       //;
       CALL FC 35
        ( IN     :=  DBD 186
        , VAN    :=  +0.0000000E+00
        , TOT    :=  +0.5000000E+00
        , DBIN   :=  DB 180
        , UIT    :=  PQW 132
        );
       //;
       CALL FC 35
        ( IN     :=  DBD 234
        , VAN    :=  +0.1000000E+03
        , TOT    :=  +0.0000000E+00
        , DBIN   :=  DB 180
        , UIT    :=  PQW 134
        );
       //;
       CALL FC 35
        ( IN     :=  DBD 258
        , VAN    :=  +0.1000000E+03
        , TOT    :=  +0.0000000E+00
        , DBIN   :=  DB 180
        , UIT    :=  PQW 144
        );
       //;
       CALL FC 35
        ( IN     :=  DBD 66
        , VAN    :=  +0.0000000E+00
        , TOT    :=  +0.1000000E+03
        , DBIN   :=  DB 180
        , UIT    :=  PQW 138
        );
       //;
       CALL FC 35
        ( IN     :=  DBD 202
        , VAN    :=  +0.0000000E+00
        , TOT    :=  +0.1000000E+03
        , DBIN   :=  DB 181
        , UIT    :=  PQW 140
        );
       //;
       CALL FC 35
        ( IN     :=  DBD 242
        , VAN    :=  +0.0000000E+00
        , TOT    :=  +0.1000000E+03
        , DBIN   :=  DB 181
        , UIT    :=  PQW 142
        );
  NETWORK
       CALL FC 35
        ( IN     :=  DBD 90
        , VAN    :=  +0.0000000E+00
        , TOT    :=  +0.1000000E+03
        , DBIN   :=  DB 180
        , UIT    :=  PQW 146
        );
       //;
       CALL FC 35
        ( IN     :=  DBD 90
        , VAN    :=  +0.0000000E+00
        , TOT    :=  +0.1000000E+03
        , DBIN   :=  DB 180
        , UIT    :=  PQW 148
        );
       //;
       CALL FC 35
        ( IN     :=  DBD 90
        , VAN    :=  +0.0000000E+00
        , TOT    :=  +0.2000000E+03
        , DBIN   :=  DB 181
        , UIT    :=  PQW 150
        );
       //;
       CALL FC 35
        ( IN     :=  DBD 42
        , VAN    :=  +0.0000000E+00
        , TOT    :=  +0.1000000E+03
        , DBIN   :=  DB 180
        , UIT    :=  PQW 152
        );
       //;
       CALL FC 35
        ( IN     :=  DBD 210
        , VAN    :=  +0.0000000E+00
        , TOT    :=  +0.1000000E+03
        , DBIN   :=  DB 180
        , UIT    :=  PQW 154
        );
       //;
       CALL FC 35
        ( IN     :=  DBD 498
        , VAN    :=  +0.0000000E+00
        , TOT    :=  +0.1000000E+03
        , DBIN   :=  DB 180
        , UIT    :=  PQW 156
        );
       //;
       CALL FC 35
        ( IN     :=  DBD 18
        , VAN    :=  +0.0000000E+00
        , TOT    :=  +0.1000000E+03
        , DBIN   :=  DB 181
        , UIT    :=  PQW 158
        );
  NETWORK
       CALL FC 35
        ( IN     :=  DBD 42
        , VAN    :=  +0.0000000E+00
        , TOT    :=  +0.1000000E+03
        , DBIN   :=  DB 181
        , UIT    :=  PQW 160
        );
       //;
       CALL FC 35
        ( IN     :=  DBD 474
        , VAN    :=  +0.1000000E+03
        , TOT    :=  +0.0000000E+00
        , DBIN   :=  DB 180
        , UIT    :=  PQW 162
        );
       //;
       CALL FC 35
        ( IN     :=  DBD 282
        , VAN    :=  +0.0000000E+00
        , TOT    :=  +0.1000000E+03
        , DBIN   :=  DB 180
        , UIT    :=  PQW 198
        );
       //;
       CALL FC 35
        ( IN     :=  DBD 306
        , VAN    :=  +0.0000000E+00
        , TOT    :=  +0.1000000E+03
        , DBIN   :=  DB 180
        , UIT    :=  PQW 166
        );
       //;
       CALL FC 35
        ( IN     :=  DBD 450
        , VAN    :=  +0.1000000E+03
        , TOT    :=  +0.0000000E+00
        , DBIN   :=  DB 180
        , UIT    :=  PQW 168
        );
       //;
       CALL FC 35
        ( IN     :=  DBD 18
        , VAN    :=  +0.0000000E+00
        , TOT    :=  +0.1000000E+03
        , DBIN   :=  DB 180
        , UIT    :=  PQW 182
        );
       //;
       CALL FC 35
        ( IN     :=  DBD 330
        , VAN    :=  +0.0000000E+00
        , TOT    :=  +0.1000000E+03
        , DBIN   :=  DB 180
        , UIT    :=  PQW 172
        );
       //;
       CALL FC 35
        ( IN     :=  DBD 206
        , VAN    :=  +0.0000000E+00
        , TOT    :=  +0.4000000E+03
        , DBIN   :=  DB 181
        , UIT    :=  PQW 174
        );
  NETWORK
       CALL FC 35
        ( IN     :=  DBD 354
        , VAN    :=  +0.0000000E+00
        , TOT    :=  +0.1000000E+03
        , DBIN   :=  DB 180
        , UIT    :=  PQW 176
        );
       //;
       CALL FC 35
        ( IN     :=  DBD 378
        , VAN    :=  +0.0000000E+00
        , TOT    :=  +0.1000000E+03
        , DBIN   :=  DB 180
        , UIT    :=  PQW 178
        );
       //;
//       CALL FC 35
//        ( IN     :=  ID 0
//        , VAN    :=  +0.0000000E+00
//        , TOT    :=  +0.0000000E+00
//        , DBIN   :=  DB 0
//        , UIT    :=  QW 0
//        );
       //;
       CALL FC 35
        ( IN     :=  DBD 402
        , VAN    :=  +0.0000000E+00
        , TOT    :=  +0.1000000E+03
        , DBIN   :=  DB 180
        , UIT    :=  PQW 184
        );
       //;
       CALL FC 35
        ( IN     :=  DBD 426
        , VAN    :=  +0.0000000E+00
        , TOT    :=  +0.1000000E+03
        , DBIN   :=  DB 180
        , UIT    :=  PQW 186
        );
       //;
       CALL FC 35
        ( IN     :=  DBD 300
        , VAN    :=  +0.0000000E+00
        , TOT    :=  +0.1000000E+03
        , DBIN   :=  DB 150
        , UIT    :=  PQW 188
        );
       //;
       CALL FC 35
        ( IN     :=  DBD 138
        , VAN    :=  +0.0000000E+00
        , TOT    :=  +0.1000000E+03
        , DBIN   :=  DB 181
        , UIT    :=  PQW 194
        );
       //;
       CALL FC 35
        ( IN     :=  DBD 238
        , VAN    :=  -0.2500000E+02
        , TOT    :=  +0.1000000E+03
        , DBIN   :=  DB 181
        , UIT    :=  PQW 192
        );
       //;
       CALL FC 35
        ( IN     :=  DBD 162
        , VAN    :=  +0.0000000E+00
        , TOT    :=  +0.1000000E+03
        , DBIN   :=  DB 181
        , UIT    :=  PQW 196
        );
       //;
       CALL FC 35
        ( IN     :=  DBD 250
        , VAN    :=  -0.2500000E+02
        , TOT    :=  +0.1000000E+03
        , DBIN   :=  DB 181
        , UIT    :=  PQW 200
        );
       //;


END_FUNCTION

FUNCTION FC 125 : VOID
  BEGIN
  NETWORK
       OPN DB 9;
       L   DBW 24;
       T   MW 254;
       //;
       OPN DB 94;
  NETWORK
       A   I 18.1;
       A   I 32.6;
       A   I 33.0;
       AN  M 178.6;
       AN  I 24.1;
       A(;
       O   I 37.0;
       O   I 15.0;
       );
       A   I 5.6;
       A   I 4.7;
       AN  M 174.7;
       =   M 170.4;
       =   Q 17.5;
  NETWORK
       A   I 34.3;
       A   I 29.6;
       =   M 170.5;
       =   Q 17.6;
  NETWORK
       A   I 49.0;
       AN  M 176.0;
       A(;
       O   M 176.1;
       O;
       A   I 26.3;
       A   M 176.2;
       );
       A   M 176.3;
       =   M 170.6;
  NETWORK
       A   I 49.0;
       AN  M 176.4;
       A(;
       O   M 176.5;
       O;
       A   I 26.7;
       A   M 176.6;
       );
       A   M 176.7;
       =   M 170.7;
  NETWORK
       OPN DB 94;
       A   M 100.0;
       L   DBW 64;
       SE  T 32;
       NOP 0;
       NOP 0;
       NOP 0;
       A   T 32;
       =   Q 16.7;
  NETWORK
       A   M 100.1;
       L   DBW 66;
       SE  T 33;
       NOP 0;
       NOP 0;
       NOP 0;
       A   T 33;
       =   Q 18.3;
  NETWORK
       A   M 109.0;
       =   Q 18.4;
       //;
       A   M 100.2;
       L   DBW 108;
       SE  T 54;
       NOP 0;
       NOP 0;
       NOP 0;
       A   T 54;
       =   Q 18.5;
       //;
       A   M 100.3;
       L   DBW 110;
       SE  T 55;
       NOP 0;
       NOP 0;
       NOP 0;
       A   T 55;
       =   Q 18.6;
       //;
       A   M 100.4;
       L   DBW 112;
       SE  T 56;
       NOP 0;
       NOP 0;
       NOP 0;
       A   T 56;
       =   Q 18.7;
       //;
       A   M 100.5;
       L   DBW 114;
       SE  T 57;
       NOP 0;
       NOP 0;
       NOP 0;
       A   T 57;
       =   Q 19.0;
       //;
       A   M 100.6;
       L   DBW 116;
       SE  T 58;
       NOP 0;
       NOP 0;
       NOP 0;
       A   T 58;
       =   Q 19.1;
       //;
       A   M 100.7;
       L   DBW 118;
       SE  T 59;
       NOP 0;
       NOP 0;
       NOP 0;
       A   T 59;
       =   Q 19.2;
       //;
  NETWORK
       A   M 101.0;
       =   Q 15.3;
       //;
       AN  M 101.1;
       =   Q 15.4;
       //;
       O   I 13.7;
       O   I 14.6;
       A   M 182.1;
       =   Q 15.5;
       //;
  NETWORK
  TITLE = ; NW verwijderd
  NETWORK
       OPN DB 9;
       L   MW 254;
       T   DBW 24;
       //;
       A   M 108.4;
       =   Q 5.0;
       //;


END_FUNCTION

FUNCTION FC 126 : VOID
  BEGIN
  NETWORK
       OPN DB 9;
       L   DBW 24;
       T   MW 254;
  NETWORK
       OPN DB 180;
       AN  M 255.1;
       A(;
       A   M 105.0;
       AN  M 106.2;
       =   M 255.1;
       A   M 255.1;
       );
       S   DBX 457.0;
  NETWORK
       AN  M 255.2;
       A(;
       A   M 105.1;
       AN  M 106.3;
       =   M 255.2;
       A   M 255.2;
       );
       S   DBX 481.0;
  NETWORK
       AN  M 255.3;
       A(;
       A   M 105.2;
       AN  M 106.4;
       =   M 255.3;
       A   M 255.3;
       );
       S   DBX 505.0;
       //;
  NETWORK
       OPN DB 181;
       L   0;
       L   DBW 226;
       ==I;
       =   M 200.0;
       //;
       OPN DB 94;
  NETWORK
       A(;
       AN  M 200.0;
       L   DBW 186;
       SD  T 93;
       NOP 0;
       NOP 0;
       NOP 0;
       A   T 93;
       );
       A   M 109.4;
       A   M 4.1;
       =   Q 12.0;
  NETWORK
       OPN DB 9;
       L   MW 254;
       T   DBW 24;


END_FUNCTION

FUNCTION FC 127 : VOID
  BEGIN
  NETWORK
  NETWORK
       L   0;
       T   MW 210;
       //;
       OPN DB 140;
       //;
       L   DBW 24;
       T   MW 212;
       L   DBW 28;
       T   MW 214;
       L   DBW 32;
       T   MW 216;
       L   W#16#0;
       T   MW 218;
  NETWORK
       OPN DB 94;
  NETWORK
       A   M 108.2;
       S   M 104.0;
       O(;
       AN  I 7.0;
       AN  I 7.1;
       );
       ON  M 108.2;
       R   M 104.0;
       A   M 104.0;
       =   M 217.0;
  NETWORK
       A   M 215.0;
       A   M 217.0;
       AN  M 213.1;
       =   M 211.1;
  NETWORK
       A   M 215.1;
       A   I 1.0;
       AN  M 213.2;
       =   M 211.2;
  NETWORK
       A   M 215.2;
       A   I 1.1;
       AN  M 213.3;
       =   M 211.3;
  NETWORK
       A(;
       O(;
       A   M 215.3;
       A(;
       A   I 3.2;
       L   DBW 34;
       SD  T 17;
       NOP 0;
       NOP 0;
       NOP 0;
       A   T 17;
       );
       );
       O   M 217.2;
       );
       AN  M 213.4;
       =   M 211.4;
  NETWORK
       A(;
       O   M 215.3;
       O   M 215.4;
       );
       AN  M 217.0;
       AN  M 213.5;
       =   M 211.5;
  NETWORK
       A(;
       O(;
       A(;
       AN  I 1.6;
       L   DBW 36;
       SD  T 18;
       NOP 0;
       NOP 0;
       NOP 0;
       A   T 18;
       );
       A   M 215.5;
       );
       O   M 217.2;
       );
       AN  M 213.6;
       =   M 211.6;
  NETWORK
       A(;
       O(;
       AN  I 3.2;
       L   DBW 38;
       SD  T 19;
       NOP 0;
       NOP 0;
       NOP 0;
       A   T 19;
       );
       O   M 217.2;
       );
       A   M 215.6;
       AN  M 213.7;
       =   M 211.7;
  NETWORK
       A(;
       O   M 217.2;
       ON  I 1.1;
       );
       A   M 215.7;
       AN  M 212.0;
       =   M 210.0;
  NETWORK
       A   M 214.0;
       AN  I 1.0;
       =   M 211.0;
  NETWORK
       CALL FC 26;
       OPN DB 140;
       //;
       L   MW 210;
       T   DBW 20;
       L   MW 212;
       T   DBW 24;
       L   MW 214;
       T   DBW 28;
       L   MW 216;
       T   DBW 32;
       L   MW 218;
       T   DBW 36;
  NETWORK
       A   M 219.1;
       S   M 18.1;
  NETWORK
       A   M 219.2;
       S   M 19.1;
  NETWORK
       A   M 219.3;
       S   M 36.1;
  NETWORK
       A   M 219.4;
       S   M 24.1;
  NETWORK
       A   M 219.5;
       S   M 24.2;
  NETWORK
       A   M 219.6;
       S   M 36.2;
  NETWORK
       A   M 219.7;
       S   M 19.2;
  NETWORK
       A   M 218.0;
       S   M 18.2;
  NETWORK


END_FUNCTION

FUNCTION FC 128 : VOID
  BEGIN
  NETWORK
  NETWORK
       L   0;
       T   MW 210;
       //;
       OPN DB 140;
       //;
       L   DBW 44;
       T   MW 212;
       L   DBW 48;
       T   MW 214;
       L   DBW 52;
       T   MW 216;
       L   W#16#0;
       T   MW 218;
  NETWORK
       OPN DB 94;
  NETWORK
       A   M 108.3;
       S   M 104.1;
       O(;
       AN  I 7.2;
       AN  I 7.3;
       );
       ON  M 108.3;
       R   M 104.1;
       A   M 104.1;
       =   M 217.0;
  NETWORK
       A   M 215.0;
       A   M 217.0;
       AN  M 213.1;
       =   M 211.1;
  NETWORK
       A   M 215.1;
       A   I 2.0;
       AN  M 213.2;
       =   M 211.2;
  NETWORK
       A   M 215.2;
       A   I 2.1;
       AN  M 213.3;
       =   M 211.3;
  NETWORK
       A(;
       O(;
       A   M 215.3;
       A(;
       A   I 3.3;
       L   DBW 100;
       SD  T 50;
       NOP 0;
       NOP 0;
       NOP 0;
       A   T 50;
       );
       );
       O   M 217.2;
       );
       AN  M 213.4;
       =   M 211.4;
  NETWORK
       A(;
       O   M 215.3;
       O   M 215.4;
       );
       AN  M 217.0;
       AN  M 213.5;
       =   M 211.5;
  NETWORK
       A(;
       O(;
       A(;
       AN  I 3.1;
       L   DBW 102;
       SD  T 51;
       NOP 0;
       NOP 0;
       NOP 0;
       A   T 51;
       );
       A   M 215.5;
       );
       O   M 217.2;
       );
       AN  M 213.6;
       =   M 211.6;
  NETWORK
       A(;
       O(;
       AN  I 3.3;
       L   DBW 104;
       SD  T 52;
       NOP 0;
       NOP 0;
       NOP 0;
       A   T 52;
       );
       O   M 217.2;
       );
       A   M 215.6;
       AN  M 213.7;
       =   M 211.7;
  NETWORK
       A(;
       O   M 217.2;
       ON  I 2.1;
       );
       A   M 215.7;
       AN  M 212.0;
       =   M 210.0;
  NETWORK
       A   M 214.0;
       AN  I 2.0;
       =   M 211.0;
  NETWORK
       CALL FC 26;
       //;
       OPN DB 140;
       //;
       L   MW 210;
       T   DBW 40;
       L   MW 212;
       T   DBW 44;
       L   MW 214;
       T   DBW 48;
       L   MW 216;
       T   DBW 52;
       L   MW 218;
       T   DBW 56;
  NETWORK
       A   M 219.1;
       S   M 26.1;
  NETWORK
       A   M 219.2;
       S   M 27.1;
  NETWORK
       A   M 219.3;
       S   M 37.1;
  NETWORK
       A   M 219.4;
       S   M 35.1;
  NETWORK
       A   M 219.5;
       S   M 35.2;
  NETWORK
       A   M 219.6;
       S   M 37.2;
  NETWORK
       A   M 219.7;
       S   M 27.2;
  NETWORK
       A   M 218.0;
       S   M 26.2;
  NETWORK


END_FUNCTION

FUNCTION FC 129 : VOID
  BEGIN
  NETWORK
       //;
       L   0;
       T   MW 210;
       T   MW 212;
       //;
       //;
       //;
       OPN DB 140;
       //;
       L   DBD 108;
       T   MD 214;
       L   DBD 116;
       T   MD 218;
       L   DBD 124;
       T   MD 222;
       L   W#16#0;
       T   MW 226;
       T   MW 228;
       //;
       //;
       CALL FC 28;
       //;
       OPN DB 138;
  NETWORK
       A   M 109.1;
       A   M 178.5;
       =   M 225.0;
  NETWORK
       A   M 225.0;
       A   M 223.0;
       AN  M 223.3;
       L   DBW 58;
       SS  T 131;
       A   M 223.3;
       R   T 131;
       NOP 0;
       NOP 0;
       A   T 131;
       =   M 223.1;
  NETWORK
       A   M 225.0;
       AN  M 223.3;
       L   DBW 60;
       SE  T 132;
       NOP 0;
       NOP 0;
       NOP 0;
       A   T 132;
       =   M 223.4;
  NETWORK
       AN  M 223.1;
       A   M 223.3;
       R   M 223.3;
  NETWORK
       O   M 223.1;
       O;
       A   M 225.0;
       A   M 221.0;
       JCN   X000;
     CALL FC 29;
  X000: NOP 0;
       //;
       CALL FC 27;
       //;
       CALL FC 30;
       //;
       OPN DB 140;
       //;
       L   MD 210;
       T   DBD 100;
       //;                      // L    MD 214
       //;                      // T    DD 54
       L   MD 218;
       T   DBD 116;
       L   MD 222;
       T   DBD 124;
       L   MD 226;
       T   DBD 132;
       //;
       A   M 233.1;
       =   Q 9.4;
       A   M 233.2;
       =   Q 9.5;
       A   M 233.3;
       =   Q 9.6;
       A   M 233.4;
       =   Q 9.7;
       A   M 233.5;
       =   Q 13.4;
       A   M 233.6;
       =   Q 13.5;
       A   M 233.7;
       =   Q 17.1;
       A   M 232.0;
       =   Q 17.2;
       A   M 232.1;
       =   Q 17.3;
       A   M 232.2;
       =   Q 17.4;
       A   M 232.3;
       =   Q 14.0;
       A   M 232.4;
       =   Q 16.0;
       A   M 232.5;
       =   Q 16.1;
       A   M 232.6;
       =   Q 16.2;
       A   M 232.7;
       =   Q 16.3;
       A   M 231.0;
       =   Q 16.4;
       A   M 231.1;
       =   Q 16.5;
       A   M 231.2;
       =   Q 16.6;
       A   M 231.3;
       =   Q 19.4;
       A   M 231.4;
       =   Q 19.5;
       A   M 231.5;
       =   Q 19.6;
       A   M 231.6;
       =   Q 19.7;
       A   M 231.7;
       =   Q 11.4;
       A   M 230.0;
       =   Q 4.4;
       //;


END_FUNCTION
